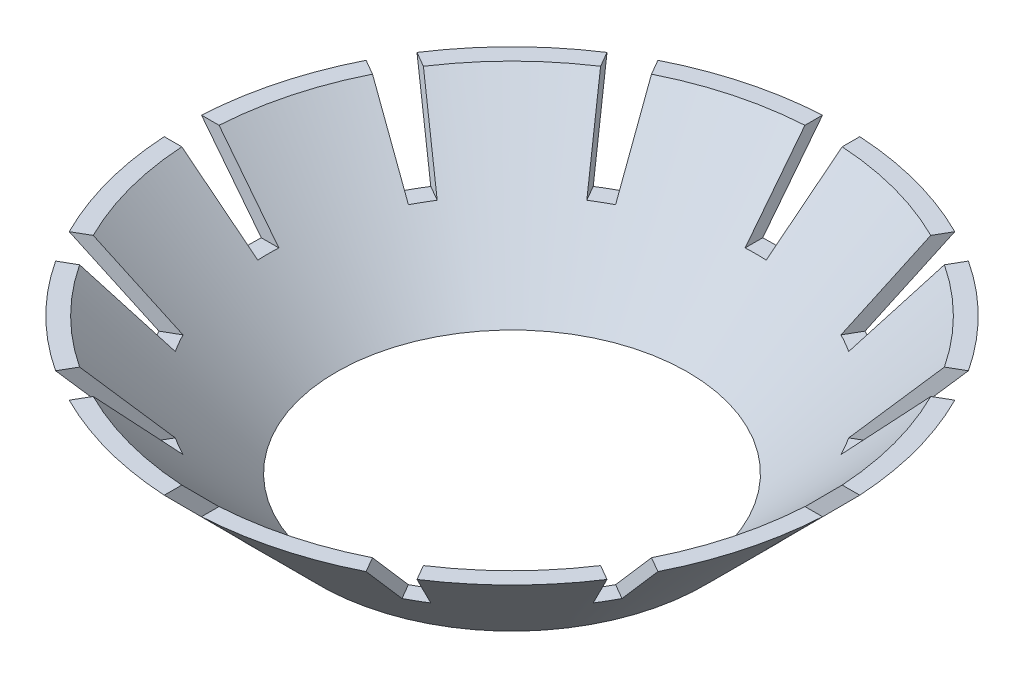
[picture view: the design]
ISO-10303-21;
HEADER;
FILE_DESCRIPTION(('STEP AP214'),'2;1');
FILE_NAME('part.step','',(''),(''),'','','');
FILE_SCHEMA(('AUTOMOTIVE_DESIGN { 1 0 10303 214 1 1 1 1 }'));
ENDSEC;
DATA;
#1=APPLICATION_CONTEXT('core data for automotive mechanical design processes');
#2=APPLICATION_PROTOCOL_DEFINITION('international standard','automotive_design',2000,#1);
#3=PRODUCT_CONTEXT('',#1,'mechanical');
#4=PRODUCT('Part','Part','',(#3));
#5=PRODUCT_RELATED_PRODUCT_CATEGORY('part','',(#4));
#6=PRODUCT_DEFINITION_FORMATION('','',#4);
#7=PRODUCT_DEFINITION_CONTEXT('part definition',#1,'design');
#8=PRODUCT_DEFINITION('design','',#6,#7);
#9=PRODUCT_DEFINITION_SHAPE('','',#8);
#10=(LENGTH_UNIT() NAMED_UNIT(*) SI_UNIT(.MILLI.,.METRE.));
#11=(NAMED_UNIT(*) PLANE_ANGLE_UNIT() SI_UNIT($,.RADIAN.));
#12=(NAMED_UNIT(*) SI_UNIT($,.STERADIAN.) SOLID_ANGLE_UNIT());
#13=UNCERTAINTY_MEASURE_WITH_UNIT(LENGTH_MEASURE(1.E-05),#10,'distance_accuracy_value','');
#14=(GEOMETRIC_REPRESENTATION_CONTEXT(3) GLOBAL_UNCERTAINTY_ASSIGNED_CONTEXT((#13)) GLOBAL_UNIT_ASSIGNED_CONTEXT((#10,
#11,#12)) REPRESENTATION_CONTEXT('',''));
#15=CARTESIAN_POINT('',(0.,0.,0.));
#16=DIRECTION('',(0.,0.,1.));
#17=DIRECTION('',(1.,0.,0.));
#18=AXIS2_PLACEMENT_3D('',#15,#16,#17);
#19=CARTESIAN_POINT('',(0.,6.59999999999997,-15.1));
#20=DIRECTION('',(0.,1.,0.));
#21=DIRECTION('',(0.,0.,1.));
#22=AXIS2_PLACEMENT_3D('',#19,#20,#21);
#23=PLANE('',#22);
#24=DIRECTION('',(0.500000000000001,0.,0.866025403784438));
#25=VECTOR('',#24,1.);
#26=CARTESIAN_POINT('',(-7.31912306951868,6.59999999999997,-10.8743023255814));
#27=LINE('',#26,#25);
#28=CARTESIAN_POINT('',(-8.74214865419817,6.59999999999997,-13.3390549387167));
#29=VERTEX_POINT('',#28);
#30=CARTESIAN_POINT('',(-8.31716705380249,6.59999999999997,-12.6029652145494));
#31=VERTEX_POINT('',#30);
#32=EDGE_CURVE('E690',#29,#31,#27,.T.);
#33=ORIENTED_EDGE('',*,*,#32,.F.);
#34=CARTESIAN_POINT('',(0.,6.59999999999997,0.));
#35=DIRECTION('',(0.,-1.,0.));
#36=DIRECTION('',(0.,0.,-1.));
#37=AXIS2_PLACEMENT_3D('',#34,#35,#36);
#38=CIRCLE('',#37,15.9485281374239);
#39=CARTESIAN_POINT('',(-13.3390549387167,6.59999999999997,-8.74214865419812));
#40=VERTEX_POINT('',#39);
#41=EDGE_CURVE('E799',#40,#29,#38,.T.);
#42=ORIENTED_EDGE('',*,*,#41,.F.);
#43=DIRECTION('',(-0.86602540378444,0.,-0.499999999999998));
#44=VECTOR('',#43,1.);
#45=CARTESIAN_POINT('',(-6.08779412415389,6.59999999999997,-4.55563127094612));
#46=LINE('',#45,#44);
#47=CARTESIAN_POINT('',(-12.6029652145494,6.59999999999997,-8.31716705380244));
#48=VERTEX_POINT('',#47);
#49=EDGE_CURVE('E792',#48,#40,#46,.T.);
#50=ORIENTED_EDGE('',*,*,#49,.F.);
#51=CARTESIAN_POINT('',(0.,6.59999999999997,0.));
#52=DIRECTION('',(0.,-1.,0.));
#53=DIRECTION('',(0.,0.,-1.));
#54=AXIS2_PLACEMENT_3D('',#51,#52,#53);
#55=CIRCLE('',#54,15.1);
#56=EDGE_CURVE('E797',#48,#31,#55,.T.);
#57=ORIENTED_EDGE('',*,*,#56,.T.);
#58=EDGE_LOOP('',(#33,#42,#50,#57));
#59=FACE_BOUND('',#58,.T.);
#60=ADVANCED_FACE('F39',(#59),#23,.T.);
#61=DIRECTION('',(0.86602540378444,0.,0.499999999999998));
#62=VECTOR('',#61,1.);
#63=CARTESIAN_POINT('',(-6.98918947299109,6.59999999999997,-2.99436872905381));
#64=LINE('',#63,#62);
#65=CARTESIAN_POINT('',(-14.2404502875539,6.59999999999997,-7.18088611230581));
#66=VERTEX_POINT('',#65);
#67=CARTESIAN_POINT('',(-13.5043605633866,6.59999999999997,-6.75590451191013));
#68=VERTEX_POINT('',#67);
#69=EDGE_CURVE('E384',#66,#68,#64,.T.);
#70=ORIENTED_EDGE('',*,*,#69,.F.);
#71=CARTESIAN_POINT('',(-15.923034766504,6.59999999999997,-0.901395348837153));
#72=VERTEX_POINT('',#71);
#73=EDGE_CURVE('E830',#72,#66,#38,.T.);
#74=ORIENTED_EDGE('',*,*,#73,.F.);
#75=DIRECTION('',(-1.,0.,0.));
#76=VECTOR('',#75,1.);
#77=CARTESIAN_POINT('',(0.,6.59999999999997,-0.901395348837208));
#78=LINE('',#77,#76);
#79=CARTESIAN_POINT('',(-15.0730715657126,6.59999999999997,-0.901395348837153));
#80=VERTEX_POINT('',#79);
#81=EDGE_CURVE('E1041',#80,#72,#78,.T.);
#82=ORIENTED_EDGE('',*,*,#81,.F.);
#83=EDGE_CURVE('E810',#80,#68,#55,.T.);
#84=ORIENTED_EDGE('',*,*,#83,.T.);
#85=EDGE_LOOP('',(#70,#74,#82,#84));
#86=FACE_BOUND('',#85,.T.);
#87=ADVANCED_FACE('F1086',(#86),#23,.T.);
#88=DIRECTION('',(1.,0.,0.));
#89=VECTOR('',#88,1.);
#90=CARTESIAN_POINT('',(0.,6.59999999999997,0.901395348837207));
#91=LINE('',#90,#89);
#92=CARTESIAN_POINT('',(-15.923034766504,6.59999999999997,0.901395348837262));
#93=VERTEX_POINT('',#92);
#94=CARTESIAN_POINT('',(-15.0730715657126,6.59999999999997,0.901395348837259));
#95=VERTEX_POINT('',#94);
#96=EDGE_CURVE('E1055',#93,#95,#91,.T.);
#97=ORIENTED_EDGE('',*,*,#96,.F.);
#98=CARTESIAN_POINT('',(-14.2404502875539,6.59999999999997,7.18088611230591));
#99=VERTEX_POINT('',#98);
#100=EDGE_CURVE('E827',#99,#93,#38,.T.);
#101=ORIENTED_EDGE('',*,*,#100,.F.);
#102=DIRECTION('',(-0.866025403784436,0.,0.500000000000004));
#103=VECTOR('',#102,1.);
#104=CARTESIAN_POINT('',(6.08779412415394,6.59999999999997,-4.55563127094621));
#105=LINE('',#104,#103);
#106=CARTESIAN_POINT('',(-13.5043605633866,6.59999999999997,6.75590451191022));
#107=VERTEX_POINT('',#106);
#108=EDGE_CURVE('E1012',#107,#99,#105,.T.);
#109=ORIENTED_EDGE('',*,*,#108,.F.);
#110=EDGE_CURVE('E809',#107,#95,#55,.T.);
#111=ORIENTED_EDGE('',*,*,#110,.T.);
#112=EDGE_LOOP('',(#97,#101,#109,#111));
#113=FACE_BOUND('',#112,.T.);
#114=ADVANCED_FACE('F1095',(#113),#23,.T.);
#115=DIRECTION('',(0.866025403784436,0.,-0.500000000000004));
#116=VECTOR('',#115,1.);
#117=CARTESIAN_POINT('',(6.98918947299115,6.59999999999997,-2.9943687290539));
#118=LINE('',#117,#116);
#119=CARTESIAN_POINT('',(-13.3390549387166,6.59999999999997,8.74214865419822));
#120=VERTEX_POINT('',#119);
#121=CARTESIAN_POINT('',(-12.6029652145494,6.59999999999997,8.31716705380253));
#122=VERTEX_POINT('',#121);
#123=EDGE_CURVE('E1036',#120,#122,#118,.T.);
#124=ORIENTED_EDGE('',*,*,#123,.F.);
#125=CARTESIAN_POINT('',(-8.74214865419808,6.59999999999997,13.3390549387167));
#126=VERTEX_POINT('',#125);
#127=EDGE_CURVE('E833',#126,#120,#38,.T.);
#128=ORIENTED_EDGE('',*,*,#127,.F.);
#129=DIRECTION('',(-0.499999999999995,0.,0.866025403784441));
#130=VECTOR('',#129,1.);
#131=CARTESIAN_POINT('',(5.75786052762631,6.59999999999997,-11.7756976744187));
#132=LINE('',#131,#130);
#133=CARTESIAN_POINT('',(-8.3171670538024,6.59999999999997,12.6029652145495));
#134=VERTEX_POINT('',#133);
#135=EDGE_CURVE('E996',#134,#126,#132,.T.);
#136=ORIENTED_EDGE('',*,*,#135,.F.);
#137=EDGE_CURVE('E1094',#134,#122,#55,.T.);
#138=ORIENTED_EDGE('',*,*,#137,.T.);
#139=EDGE_LOOP('',(#124,#128,#136,#138));
#140=FACE_BOUND('',#139,.T.);
#141=ADVANCED_FACE('F1191',(#140),#23,.T.);
#142=DIRECTION('',(0.499999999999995,0.,-0.866025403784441));
#143=VECTOR('',#142,1.);
#144=CARTESIAN_POINT('',(7.31912306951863,6.59999999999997,-10.8743023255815));
#145=LINE('',#144,#143);
#146=CARTESIAN_POINT('',(-7.18088611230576,6.59999999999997,14.2404502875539));
#147=VERTEX_POINT('',#146);
#148=CARTESIAN_POINT('',(-6.75590451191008,6.59999999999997,13.5043605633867));
#149=VERTEX_POINT('',#148);
#150=EDGE_CURVE('E1007',#147,#149,#145,.T.);
#151=ORIENTED_EDGE('',*,*,#150,.F.);
#152=CARTESIAN_POINT('',(-0.901395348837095,6.59999999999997,15.923034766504));
#153=VERTEX_POINT('',#152);
#154=EDGE_CURVE('E836',#153,#147,#38,.T.);
#155=ORIENTED_EDGE('',*,*,#154,.F.);
#156=DIRECTION('',(0.,0.,1.));
#157=VECTOR('',#156,1.);
#158=CARTESIAN_POINT('',(-0.901395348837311,6.59999999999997,-15.1));
#159=LINE('',#158,#157);
#160=CARTESIAN_POINT('',(-0.901395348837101,6.59999999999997,15.0730715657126));
#161=VERTEX_POINT('',#160);
#162=EDGE_CURVE('E968',#161,#153,#159,.T.);
#163=ORIENTED_EDGE('',*,*,#162,.F.);
#164=EDGE_CURVE('E1100',#161,#149,#55,.T.);
#165=ORIENTED_EDGE('',*,*,#164,.T.);
#166=EDGE_LOOP('',(#151,#155,#163,#165));
#167=FACE_BOUND('',#166,.T.);
#168=ADVANCED_FACE('F1189',(#167),#23,.T.);
#169=DIRECTION('',(0.,0.,-1.));
#170=VECTOR('',#169,1.);
#171=CARTESIAN_POINT('',(0.9013953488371,6.59999999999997,-15.1));
#172=LINE('',#171,#170);
#173=CARTESIAN_POINT('',(0.901395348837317,6.59999999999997,15.923034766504));
#174=VERTEX_POINT('',#173);
#175=CARTESIAN_POINT('',(0.901395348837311,6.59999999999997,15.0730715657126));
#176=VERTEX_POINT('',#175);
#177=EDGE_CURVE('E980',#174,#176,#172,.T.);
#178=ORIENTED_EDGE('',*,*,#177,.F.);
#179=CARTESIAN_POINT('',(7.18088611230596,6.59999999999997,14.2404502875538));
#180=VERTEX_POINT('',#179);
#181=EDGE_CURVE('E843',#180,#174,#38,.T.);
#182=ORIENTED_EDGE('',*,*,#181,.F.);
#183=DIRECTION('',(0.500000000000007,0.,0.866025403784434));
#184=VECTOR('',#183,1.);
#185=CARTESIAN_POINT('',(-7.31912306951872,6.59999999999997,-10.8743023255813));
#186=LINE('',#185,#184);
#187=CARTESIAN_POINT('',(6.75590451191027,6.59999999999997,13.5043605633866));
#188=VERTEX_POINT('',#187);
#189=EDGE_CURVE('E934',#188,#180,#186,.T.);
#190=ORIENTED_EDGE('',*,*,#189,.F.);
#191=EDGE_CURVE('E1102',#188,#176,#55,.T.);
#192=ORIENTED_EDGE('',*,*,#191,.T.);
#193=EDGE_LOOP('',(#178,#182,#190,#192));
#194=FACE_BOUND('',#193,.T.);
#195=ADVANCED_FACE('F1186',(#194),#23,.T.);
#196=DIRECTION('',(-0.500000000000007,0.,-0.866025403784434));
#197=VECTOR('',#196,1.);
#198=CARTESIAN_POINT('',(-5.75786052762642,6.59999999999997,-11.7756976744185));
#199=LINE('',#198,#197);
#200=CARTESIAN_POINT('',(8.74214865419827,6.59999999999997,13.3390549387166));
#201=VERTEX_POINT('',#200);
#202=CARTESIAN_POINT('',(8.31716705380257,6.59999999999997,12.6029652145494));
#203=VERTEX_POINT('',#202);
#204=EDGE_CURVE('E965',#201,#203,#199,.T.);
#205=ORIENTED_EDGE('',*,*,#204,.F.);
#206=CARTESIAN_POINT('',(13.3390549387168,6.59999999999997,8.74214865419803));
#207=VERTEX_POINT('',#206);
#208=EDGE_CURVE('E846',#207,#201,#38,.T.);
#209=ORIENTED_EDGE('',*,*,#208,.F.);
#210=DIRECTION('',(0.866025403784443,0.,0.499999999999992));
#211=VECTOR('',#210,1.);
#212=CARTESIAN_POINT('',(-6.98918947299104,6.59999999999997,-2.99436872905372));
#213=LINE('',#212,#211);
#214=CARTESIAN_POINT('',(12.6029652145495,6.59999999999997,8.31716705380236));
#215=VERTEX_POINT('',#214);
#216=EDGE_CURVE('E454',#215,#207,#213,.T.);
#217=ORIENTED_EDGE('',*,*,#216,.F.);
#218=EDGE_CURVE('E1106',#215,#203,#55,.T.);
#219=ORIENTED_EDGE('',*,*,#218,.T.);
#220=EDGE_LOOP('',(#205,#209,#217,#219));
#221=FACE_BOUND('',#220,.T.);
#222=ADVANCED_FACE('F1119',(#221),#23,.T.);
#223=DIRECTION('',(-0.866025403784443,0.,-0.499999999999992));
#224=VECTOR('',#223,1.);
#225=CARTESIAN_POINT('',(-6.08779412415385,6.59999999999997,-4.55563127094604));
#226=LINE('',#225,#224);
#227=CARTESIAN_POINT('',(14.240450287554,6.59999999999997,7.18088611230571));
#228=VERTEX_POINT('',#227);
#229=CARTESIAN_POINT('',(13.5043605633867,6.59999999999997,6.75590451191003));
#230=VERTEX_POINT('',#229);
#231=EDGE_CURVE('E927',#228,#230,#226,.T.);
#232=ORIENTED_EDGE('',*,*,#231,.F.);
#233=CARTESIAN_POINT('',(15.923034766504,6.59999999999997,0.90139534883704));
#234=VERTEX_POINT('',#233);
#235=EDGE_CURVE('E854',#234,#228,#38,.T.);
#236=ORIENTED_EDGE('',*,*,#235,.F.);
#237=DIRECTION('',(1.,0.,0.));
#238=VECTOR('',#237,1.);
#239=CARTESIAN_POINT('',(1.67605719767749E-13,6.59999999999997,0.901395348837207));
#240=LINE('',#239,#238);
#241=CARTESIAN_POINT('',(15.0730715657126,6.59999999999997,0.901395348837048));
#242=VERTEX_POINT('',#241);
#243=EDGE_CURVE('E874',#242,#234,#240,.T.);
#244=ORIENTED_EDGE('',*,*,#243,.F.);
#245=EDGE_CURVE('E918',#242,#230,#55,.T.);
#246=ORIENTED_EDGE('',*,*,#245,.T.);
#247=EDGE_LOOP('',(#232,#236,#244,#246));
#248=FACE_BOUND('',#247,.T.);
#249=ADVANCED_FACE('F921',(#248),#23,.T.);
#250=DIRECTION('',(-1.,0.,0.));
#251=VECTOR('',#250,1.);
#252=CARTESIAN_POINT('',(1.48722489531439E-13,6.59999999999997,-0.901395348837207));
#253=LINE('',#252,#251);
#254=CARTESIAN_POINT('',(15.923034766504,6.59999999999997,-0.901395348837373));
#255=VERTEX_POINT('',#254);
#256=CARTESIAN_POINT('',(15.0730715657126,6.59999999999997,-0.901395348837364));
#257=VERTEX_POINT('',#256);
#258=EDGE_CURVE('E457',#255,#257,#253,.T.);
#259=ORIENTED_EDGE('',*,*,#258,.F.);
#260=CARTESIAN_POINT('',(14.2404502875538,6.59999999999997,-7.18088611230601));
#261=VERTEX_POINT('',#260);
#262=EDGE_CURVE('E453',#261,#255,#38,.T.);
#263=ORIENTED_EDGE('',*,*,#262,.F.);
#264=DIRECTION('',(0.866025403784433,0.,-0.50000000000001));
#265=VECTOR('',#264,1.);
#266=CARTESIAN_POINT('',(6.98918947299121,6.59999999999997,-2.994368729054));
#267=LINE('',#266,#265);
#268=CARTESIAN_POINT('',(13.5043605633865,6.59999999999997,-6.75590451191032));
#269=VERTEX_POINT('',#268);
#270=EDGE_CURVE('E878',#269,#261,#267,.T.);
#271=ORIENTED_EDGE('',*,*,#270,.F.);
#272=EDGE_CURVE('E911',#269,#257,#55,.T.);
#273=ORIENTED_EDGE('',*,*,#272,.T.);
#274=EDGE_LOOP('',(#259,#263,#271,#273));
#275=FACE_BOUND('',#274,.T.);
#276=ADVANCED_FACE('F915',(#275),#23,.T.);
#277=DIRECTION('',(-0.866025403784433,0.,0.50000000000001));
#278=VECTOR('',#277,1.);
#279=CARTESIAN_POINT('',(6.08779412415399,6.59999999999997,-4.5556312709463));
#280=LINE('',#279,#278);
#281=CARTESIAN_POINT('',(13.3390549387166,6.59999999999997,-8.74214865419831));
#282=VERTEX_POINT('',#281);
#283=CARTESIAN_POINT('',(12.6029652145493,6.59999999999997,-8.31716705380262));
#284=VERTEX_POINT('',#283);
#285=EDGE_CURVE('E866',#282,#284,#280,.T.);
#286=ORIENTED_EDGE('',*,*,#285,.F.);
#287=CARTESIAN_POINT('',(8.74214865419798,6.59999999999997,-13.3390549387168));
#288=VERTEX_POINT('',#287);
#289=EDGE_CURVE('E742',#288,#282,#38,.T.);
#290=ORIENTED_EDGE('',*,*,#289,.F.);
#291=DIRECTION('',(0.499999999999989,0.,-0.866025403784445));
#292=VECTOR('',#291,1.);
#293=CARTESIAN_POINT('',(7.31912306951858,6.59999999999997,-10.8743023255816));
#294=LINE('',#293,#292);
#295=CARTESIAN_POINT('',(8.31716705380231,6.59999999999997,-12.6029652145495));
#296=VERTEX_POINT('',#295);
#297=EDGE_CURVE('E354',#296,#288,#294,.T.);
#298=ORIENTED_EDGE('',*,*,#297,.F.);
#299=EDGE_CURVE('E739',#296,#284,#55,.T.);
#300=ORIENTED_EDGE('',*,*,#299,.T.);
#301=EDGE_LOOP('',(#286,#290,#298,#300));
#302=FACE_BOUND('',#301,.T.);
#303=ADVANCED_FACE('F867',(#302),#23,.T.);
#304=DIRECTION('',(-0.499999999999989,0.,0.866025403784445));
#305=VECTOR('',#304,1.);
#306=CARTESIAN_POINT('',(5.75786052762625,6.59999999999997,-11.7756976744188));
#307=LINE('',#306,#305);
#308=CARTESIAN_POINT('',(7.18088611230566,6.59999999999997,-14.240450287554));
#309=VERTEX_POINT('',#308);
#310=CARTESIAN_POINT('',(6.75590451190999,6.59999999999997,-13.5043605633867));
#311=VERTEX_POINT('',#310);
#312=EDGE_CURVE('E360',#309,#311,#307,.T.);
#313=ORIENTED_EDGE('',*,*,#312,.F.);
#314=CARTESIAN_POINT('',(0.901395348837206,6.59999999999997,-15.923034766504));
#315=VERTEX_POINT('',#314);
#316=EDGE_CURVE('E740',#315,#309,#38,.T.);
#317=ORIENTED_EDGE('',*,*,#316,.F.);
#318=DIRECTION('',(0.,0.,-1.));
#319=VECTOR('',#318,1.);
#320=CARTESIAN_POINT('',(0.901395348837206,6.59999999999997,-15.1));
#321=LINE('',#320,#319);
#322=CARTESIAN_POINT('',(0.901395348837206,6.59999999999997,-15.0730715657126));
#323=VERTEX_POINT('',#322);
#324=EDGE_CURVE('E720',#323,#315,#321,.T.);
#325=ORIENTED_EDGE('',*,*,#324,.F.);
#326=EDGE_CURVE('E732',#323,#311,#55,.T.);
#327=ORIENTED_EDGE('',*,*,#326,.T.);
#328=EDGE_LOOP('',(#313,#317,#325,#327));
#329=FACE_BOUND('',#328,.T.);
#330=ADVANCED_FACE('F821',(#329),#23,.T.);
#331=CARTESIAN_POINT('',(0.,0.,-8.5));
#332=DIRECTION('',(0.,-1.,0.));
#333=DIRECTION('',(0.,0.,-1.));
#334=AXIS2_PLACEMENT_3D('',#331,#332,#333);
#335=PLANE('',#334);
#336=CARTESIAN_POINT('',(0.,0.,0.));
#337=DIRECTION('',(0.,-1.,0.));
#338=DIRECTION('',(0.,0.,-1.));
#339=AXIS2_PLACEMENT_3D('',#336,#337,#338);
#340=CIRCLE('',#339,9.34852813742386);
#341=CARTESIAN_POINT('',(0.,0.,-9.34852813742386));
#342=VERTEX_POINT('',#341);
#343=EDGE_CURVE('E738',#342,#342,#340,.T.);
#344=ORIENTED_EDGE('',*,*,#343,.T.);
#345=EDGE_LOOP('',(#344));
#346=FACE_BOUND('',#345,.T.);
#347=CARTESIAN_POINT('',(0.,0.,0.));
#348=DIRECTION('',(0.,-1.,0.));
#349=DIRECTION('',(0.,0.,-1.));
#350=AXIS2_PLACEMENT_3D('',#347,#348,#349);
#351=CIRCLE('',#350,8.5);
#352=CARTESIAN_POINT('',(0.,0.,-8.5));
#353=VERTEX_POINT('',#352);
#354=EDGE_CURVE('E729',#353,#353,#351,.T.);
#355=ORIENTED_EDGE('',*,*,#354,.F.);
#356=EDGE_LOOP('',(#355));
#357=FACE_BOUND('',#356,.T.);
#358=ADVANCED_FACE('F41',(#346,#357),#335,.T.);
#359=CARTESIAN_POINT('',(0.,0.,0.));
#360=DIRECTION('',(0.,1.,0.));
#361=DIRECTION('',(0.,0.,1.));
#362=AXIS2_PLACEMENT_3D('',#359,#360,#361);
#363=CONICAL_SURFACE('',#362,9.34852813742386,0.78539816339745);
#364=CARTESIAN_POINT('',(-6.7606738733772,3.2998,-10.6898780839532));
#365=CARTESIAN_POINT('',(-7.09100219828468,3.8497129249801,-11.1315790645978));
#366=CARTESIAN_POINT('',(-7.42129926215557,4.39970272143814,-11.573207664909));
#367=CARTESIAN_POINT('',(-8.08183086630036,5.49983605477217,-12.4563201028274));
#368=CARTESIAN_POINT('',(-8.41206540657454,6.04997959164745,-12.8978039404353));
#369=CARTESIAN_POINT('',(-8.74226868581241,6.60019999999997,-13.3392153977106));
#370=B_SPLINE_CURVE_WITH_KNOTS('',3,(#364,#365,#366,#367,#368,#369),.UNSPECIFIED.,.F.,.F.,(4,2,
4),(0.,2.33657585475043,4.67315169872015),.UNSPECIFIED.);
#371=CARTESIAN_POINT('',(-6.76079401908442,3.3,-10.690038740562));
#372=VERTEX_POINT('',#371);
#373=EDGE_CURVE('E689',#372,#29,#370,.T.);
#374=ORIENTED_EDGE('',*,*,#373,.F.);
#375=CARTESIAN_POINT('',(0.,3.3,0.));
#376=DIRECTION('',(0.,-1.,0.));
#377=DIRECTION('',(0.,0.,-1.));
#378=AXIS2_PLACEMENT_3D('',#375,#376,#377);
#379=CIRCLE('',#378,12.6485281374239);
#380=CARTESIAN_POINT('',(-5.87744810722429,3.3,-11.200038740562));
#381=VERTEX_POINT('',#380);
#382=EDGE_CURVE('E382',#381,#372,#379,.F.);
#383=ORIENTED_EDGE('',*,*,#382,.F.);
#384=CARTESIAN_POINT('',(-7.18096505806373,6.60019999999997,-14.240634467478));
#385=CARTESIAN_POINT('',(-6.96379316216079,6.04997959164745,-13.7339643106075));
#386=CARTESIAN_POINT('',(-6.74657421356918,5.49983605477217,-13.227230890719));
#387=CARTESIAN_POINT('',(-6.31204221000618,4.39970272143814,-12.2136375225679));
#388=CARTESIAN_POINT('',(-6.09472915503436,3.84971292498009,-11.7067775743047));
#389=CARTESIAN_POINT('',(-5.87736904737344,3.2998,-11.199854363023));
#390=B_SPLINE_CURVE_WITH_KNOTS('',3,(#384,#385,#386,#387,#388,#389),.UNSPECIFIED.,.F.,.F.,(4,2,
4),(0.,2.33657584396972,4.67315169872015),.UNSPECIFIED.);
#391=CARTESIAN_POINT('',(-7.18088611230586,6.59999999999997,-14.2404502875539));
#392=VERTEX_POINT('',#391);
#393=EDGE_CURVE('E389',#392,#381,#390,.T.);
#394=ORIENTED_EDGE('',*,*,#393,.F.);
#395=CARTESIAN_POINT('',(-0.901395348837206,6.59999999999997,-15.923034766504));
#396=VERTEX_POINT('',#395);
#397=EDGE_CURVE('E737',#392,#396,#38,.T.);
#398=ORIENTED_EDGE('',*,*,#397,.T.);
#399=CARTESIAN_POINT('',(-0.509976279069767,3.2998,-12.6380429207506));
#400=CARTESIAN_POINT('',(-0.575198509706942,3.84971292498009,-13.185731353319));
#401=CARTESIAN_POINT('',(-0.640429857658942,4.39970272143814,-13.7333414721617));
#402=CARTESIAN_POINT('',(-0.770910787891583,5.49983605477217,-14.8284050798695));
#403=CARTESIAN_POINT('',(-0.83616037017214,6.04997959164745,-15.3758585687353));
#404=CARTESIAN_POINT('',(-0.901419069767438,6.60019999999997,-15.9232337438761));
#405=B_SPLINE_CURVE_WITH_KNOTS('',3,(#399,#400,#401,#402,#403,#404),.UNSPECIFIED.,.F.,.F.,(4,2,
4),(0.,2.33657585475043,4.67315169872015),.UNSPECIFIED.);
#406=CARTESIAN_POINT('',(-0.51,3.3,-12.6382421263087));
#407=VERTEX_POINT('',#406);
#408=EDGE_CURVE('E725',#407,#396,#405,.T.);
#409=ORIENTED_EDGE('',*,*,#408,.F.);
#410=CARTESIAN_POINT('',(0.,3.3,0.));
#411=DIRECTION('',(0.,-1.,0.));
#412=DIRECTION('',(0.,0.,-1.));
#413=AXIS2_PLACEMENT_3D('',#410,#411,#412);
#414=CIRCLE('',#413,12.6485281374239);
#415=CARTESIAN_POINT('',(0.51,3.3,-12.6382421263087));
#416=VERTEX_POINT('',#415);
#417=EDGE_CURVE('E822',#416,#407,#414,.F.);
#418=ORIENTED_EDGE('',*,*,#417,.F.);
#419=CARTESIAN_POINT('',(0.901419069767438,6.60019999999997,-15.9232337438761));
#420=CARTESIAN_POINT('',(0.83616037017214,6.04997959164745,-15.3758585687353));
#421=CARTESIAN_POINT('',(0.770910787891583,5.49983605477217,-14.8284050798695));
#422=CARTESIAN_POINT('',(0.640429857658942,4.39970272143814,-13.7333414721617));
#423=CARTESIAN_POINT('',(0.575198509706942,3.84971292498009,-13.185731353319));
#424=CARTESIAN_POINT('',(0.509976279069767,3.2998,-12.6380429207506));
#425=B_SPLINE_CURVE_WITH_KNOTS('',3,(#419,#420,#421,#422,#423,#424),.UNSPECIFIED.,.F.,.F.,(4,2,
4),(0.,2.33657584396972,4.67315169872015),.UNSPECIFIED.);
#426=EDGE_CURVE('E708',#315,#416,#425,.T.);
#427=ORIENTED_EDGE('',*,*,#426,.F.);
#428=ORIENTED_EDGE('',*,*,#316,.T.);
#429=CARTESIAN_POINT('',(5.87736904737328,3.2998,-11.1998543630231));
#430=CARTESIAN_POINT('',(6.0947291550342,3.8497129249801,-11.7067775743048));
#431=CARTESIAN_POINT('',(6.31204221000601,4.39970272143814,-12.213637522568));
#432=CARTESIAN_POINT('',(6.746574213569,5.49983605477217,-13.2272308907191));
#433=CARTESIAN_POINT('',(6.9637931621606,6.04997959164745,-13.7339643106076));
#434=CARTESIAN_POINT('',(7.18096505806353,6.60019999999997,-14.2406344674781));
#435=B_SPLINE_CURVE_WITH_KNOTS('',3,(#429,#430,#431,#432,#433,#434),.UNSPECIFIED.,.F.,.F.,(4,2,
4),(0.,2.33657585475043,4.67315169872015),.UNSPECIFIED.);
#436=CARTESIAN_POINT('',(5.87744810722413,3.3,-11.2000387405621));
#437=VERTEX_POINT('',#436);
#438=EDGE_CURVE('E380',#437,#309,#435,.T.);
#439=ORIENTED_EDGE('',*,*,#438,.F.);
#440=CARTESIAN_POINT('',(6.76079401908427,3.3,-10.6900387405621));
#441=VERTEX_POINT('',#440);
#442=EDGE_CURVE('E364',#441,#437,#379,.F.);
#443=ORIENTED_EDGE('',*,*,#442,.F.);
#444=CARTESIAN_POINT('',(8.74226868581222,6.60019999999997,-13.3392153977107));
#445=CARTESIAN_POINT('',(8.41206540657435,6.04997959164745,-12.8978039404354));
#446=CARTESIAN_POINT('',(8.08183086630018,5.49983605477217,-12.4563201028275));
#447=CARTESIAN_POINT('',(7.42129926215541,4.39970272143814,-11.5732076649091));
#448=CARTESIAN_POINT('',(7.09100219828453,3.8497129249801,-11.1315790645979));
#449=CARTESIAN_POINT('',(6.76067387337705,3.2998,-10.6898780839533));
#450=B_SPLINE_CURVE_WITH_KNOTS('',3,(#444,#445,#446,#447,#448,#449),.UNSPECIFIED.,.F.,.F.,(4,2,
4),(0.,2.33657584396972,4.67315169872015),.UNSPECIFIED.);
#451=EDGE_CURVE('E350',#288,#441,#450,.T.);
#452=ORIENTED_EDGE('',*,*,#451,.F.);
#453=ORIENTED_EDGE('',*,*,#289,.T.);
#454=CARTESIAN_POINT('',(10.6898780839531,3.2998,-6.76067387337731));
#455=CARTESIAN_POINT('',(11.1315790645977,3.8497129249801,-7.0910021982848));
#456=CARTESIAN_POINT('',(11.5732076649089,4.39970272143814,-7.42129926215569));
#457=CARTESIAN_POINT('',(12.4563201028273,5.49983605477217,-8.08183086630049));
#458=CARTESIAN_POINT('',(12.8978039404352,6.04997959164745,-8.41206540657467));
#459=CARTESIAN_POINT('',(13.3392153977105,6.60019999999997,-8.74226868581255));
#460=B_SPLINE_CURVE_WITH_KNOTS('',3,(#454,#455,#456,#457,#458,#459),.UNSPECIFIED.,.F.,.F.,(4,2,
4),(0.,2.33657585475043,4.67315169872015),.UNSPECIFIED.);
#461=CARTESIAN_POINT('',(10.6900387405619,3.3,-6.76079401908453));
#462=VERTEX_POINT('',#461);
#463=EDGE_CURVE('E862',#462,#282,#460,.T.);
#464=ORIENTED_EDGE('',*,*,#463,.F.);
#465=CARTESIAN_POINT('',(11.2000387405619,3.3,-5.87744810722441));
#466=VERTEX_POINT('',#465);
#467=EDGE_CURVE('E377',#466,#462,#379,.F.);
#468=ORIENTED_EDGE('',*,*,#467,.F.);
#469=CARTESIAN_POINT('',(14.2406344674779,6.60019999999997,-7.18096505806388));
#470=CARTESIAN_POINT('',(13.7339643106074,6.04997959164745,-6.96379316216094));
#471=CARTESIAN_POINT('',(13.2272308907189,5.49983605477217,-6.74657421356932));
#472=CARTESIAN_POINT('',(12.2136375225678,4.39970272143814,-6.31204221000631));
#473=CARTESIAN_POINT('',(11.7067775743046,3.8497129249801,-6.09472915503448));
#474=CARTESIAN_POINT('',(11.1998543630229,3.2998,-5.87736904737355));
#475=B_SPLINE_CURVE_WITH_KNOTS('',3,(#469,#470,#471,#472,#473,#474),.UNSPECIFIED.,.F.,.F.,(4,2,
4),(0.,2.33657584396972,4.67315169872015),.UNSPECIFIED.);
#476=EDGE_CURVE('E875',#261,#466,#475,.T.);
#477=ORIENTED_EDGE('',*,*,#476,.F.);
#478=ORIENTED_EDGE('',*,*,#262,.T.);
#479=CARTESIAN_POINT('',(12.6380429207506,3.2998,-0.5099762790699));
#480=CARTESIAN_POINT('',(13.185731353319,3.8497129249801,-0.57519850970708));
#481=CARTESIAN_POINT('',(13.7333414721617,4.39970272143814,-0.640429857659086));
#482=CARTESIAN_POINT('',(14.8284050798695,5.49983605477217,-0.770910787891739));
#483=CARTESIAN_POINT('',(15.3758585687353,6.04997959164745,-0.836160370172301));
#484=CARTESIAN_POINT('',(15.9232337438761,6.60019999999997,-0.901419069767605));
#485=B_SPLINE_CURVE_WITH_KNOTS('',3,(#479,#480,#481,#482,#483,#484),.UNSPECIFIED.,.F.,.F.,(4,2,
4),(0.,2.33657585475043,4.67315169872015),.UNSPECIFIED.);
#486=CARTESIAN_POINT('',(12.6382421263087,3.3,-0.510000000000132));
#487=VERTEX_POINT('',#486);
#488=EDGE_CURVE('E444',#487,#255,#485,.T.);
#489=ORIENTED_EDGE('',*,*,#488,.F.);
#490=CARTESIAN_POINT('',(12.6382421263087,3.3,0.509999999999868));
#491=VERTEX_POINT('',#490);
#492=EDGE_CURVE('E385',#491,#487,#379,.F.);
#493=ORIENTED_EDGE('',*,*,#492,.F.);
#494=CARTESIAN_POINT('',(15.9232337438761,6.60019999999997,0.901419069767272));
#495=CARTESIAN_POINT('',(15.3758585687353,6.04997959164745,0.836160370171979));
#496=CARTESIAN_POINT('',(14.8284050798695,5.49983605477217,0.770910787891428));
#497=CARTESIAN_POINT('',(13.7333414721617,4.39970272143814,0.640429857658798));
#498=CARTESIAN_POINT('',(13.185731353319,3.84971292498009,0.575198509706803));
#499=CARTESIAN_POINT('',(12.6380429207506,3.2998,0.509976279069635));
#500=B_SPLINE_CURVE_WITH_KNOTS('',3,(#494,#495,#496,#497,#498,#499),.UNSPECIFIED.,.F.,.F.,(4,2,
4),(0.,2.33657584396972,4.67315169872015),.UNSPECIFIED.);
#501=EDGE_CURVE('E458',#234,#491,#500,.T.);
#502=ORIENTED_EDGE('',*,*,#501,.F.);
#503=ORIENTED_EDGE('',*,*,#235,.T.);
#504=CARTESIAN_POINT('',(11.1998543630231,3.2998,5.87736904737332));
#505=CARTESIAN_POINT('',(11.7067775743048,3.8497129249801,6.09472915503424));
#506=CARTESIAN_POINT('',(12.213637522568,4.39970272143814,6.31204221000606));
#507=CARTESIAN_POINT('',(13.2272308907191,5.49983605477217,6.74657421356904));
#508=CARTESIAN_POINT('',(13.7339643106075,6.04997959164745,6.96379316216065));
#509=CARTESIAN_POINT('',(14.2406344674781,6.60019999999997,7.18096505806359));
#510=B_SPLINE_CURVE_WITH_KNOTS('',3,(#504,#505,#506,#507,#508,#509),.UNSPECIFIED.,.F.,.F.,(4,2,
4),(0.,2.33657585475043,4.67315169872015),.UNSPECIFIED.);
#511=CARTESIAN_POINT('',(11.200038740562,3.3,5.87744810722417));
#512=VERTEX_POINT('',#511);
#513=EDGE_CURVE('E929',#512,#228,#510,.T.);
#514=ORIENTED_EDGE('',*,*,#513,.F.);
#515=CARTESIAN_POINT('',(10.690038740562,3.3,6.76079401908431));
#516=VERTEX_POINT('',#515);
#517=EDGE_CURVE('E416',#516,#512,#379,.F.);
#518=ORIENTED_EDGE('',*,*,#517,.F.);
#519=CARTESIAN_POINT('',(13.3392153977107,6.60019999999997,8.74226868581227));
#520=CARTESIAN_POINT('',(12.8978039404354,6.04997959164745,8.4120654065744));
#521=CARTESIAN_POINT('',(12.4563201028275,5.49983605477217,8.08183086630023));
#522=CARTESIAN_POINT('',(11.573207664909,4.39970272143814,7.42129926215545));
#523=CARTESIAN_POINT('',(11.1315790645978,3.8497129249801,7.09100219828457));
#524=CARTESIAN_POINT('',(10.6898780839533,3.2998,6.76067387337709));
#525=B_SPLINE_CURVE_WITH_KNOTS('',3,(#519,#520,#521,#522,#523,#524),.UNSPECIFIED.,.F.,.F.,(4,2,
4),(0.,2.33657584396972,4.67315169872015),.UNSPECIFIED.);
#526=EDGE_CURVE('E460',#207,#516,#525,.T.);
#527=ORIENTED_EDGE('',*,*,#526,.F.);
#528=ORIENTED_EDGE('',*,*,#208,.T.);
#529=CARTESIAN_POINT('',(6.76067387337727,3.2998,10.6898780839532));
#530=CARTESIAN_POINT('',(7.09100219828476,3.8497129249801,11.1315790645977));
#531=CARTESIAN_POINT('',(7.42129926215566,4.39970272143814,11.5732076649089));
#532=CARTESIAN_POINT('',(8.08183086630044,5.49983605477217,12.4563201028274));
#533=CARTESIAN_POINT('',(8.41206540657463,6.04997959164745,12.8978039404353));
#534=CARTESIAN_POINT('',(8.74226868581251,6.60019999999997,13.3392153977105));
#535=B_SPLINE_CURVE_WITH_KNOTS('',3,(#529,#530,#531,#532,#533,#534),.UNSPECIFIED.,.F.,.F.,(4,2,
4),(0.,2.33657585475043,4.67315169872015),.UNSPECIFIED.);
#536=CARTESIAN_POINT('',(6.76079401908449,3.3,10.6900387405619));
#537=VERTEX_POINT('',#536);
#538=EDGE_CURVE('E963',#537,#201,#535,.T.);
#539=ORIENTED_EDGE('',*,*,#538,.F.);
#540=CARTESIAN_POINT('',(5.87744810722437,3.3,11.2000387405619));
#541=VERTEX_POINT('',#540);
#542=EDGE_CURVE('E411',#541,#537,#379,.F.);
#543=ORIENTED_EDGE('',*,*,#542,.F.);
#544=CARTESIAN_POINT('',(7.18096505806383,6.60019999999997,14.240634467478));
#545=CARTESIAN_POINT('',(6.96379316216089,6.04997959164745,13.7339643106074));
#546=CARTESIAN_POINT('',(6.74657421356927,5.49983605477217,13.2272308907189));
#547=CARTESIAN_POINT('',(6.31204221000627,4.39970272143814,12.2136375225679));
#548=CARTESIAN_POINT('',(6.09472915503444,3.8497129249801,11.7067775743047));
#549=CARTESIAN_POINT('',(5.87736904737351,3.2998,11.1998543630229));
#550=B_SPLINE_CURVE_WITH_KNOTS('',3,(#544,#545,#546,#547,#548,#549),.UNSPECIFIED.,.F.,.F.,(4,2,
4),(0.,2.33657584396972,4.67315169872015),.UNSPECIFIED.);
#551=EDGE_CURVE('E956',#180,#541,#550,.T.);
#552=ORIENTED_EDGE('',*,*,#551,.F.);
#553=ORIENTED_EDGE('',*,*,#181,.T.);
#554=CARTESIAN_POINT('',(0.509976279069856,3.2998,12.6380429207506));
#555=CARTESIAN_POINT('',(0.575198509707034,3.8497129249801,13.185731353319));
#556=CARTESIAN_POINT('',(0.640429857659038,4.39970272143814,13.7333414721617));
#557=CARTESIAN_POINT('',(0.770910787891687,5.49983605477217,14.8284050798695));
#558=CARTESIAN_POINT('',(0.836160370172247,6.04997959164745,15.3758585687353));
#559=CARTESIAN_POINT('',(0.90141906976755,6.60019999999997,15.9232337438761));
#560=B_SPLINE_CURVE_WITH_KNOTS('',3,(#554,#555,#556,#557,#558,#559),.UNSPECIFIED.,.F.,.F.,(4,2,
4),(0.,2.33657585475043,4.67315169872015),.UNSPECIFIED.);
#561=CARTESIAN_POINT('',(0.510000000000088,3.3,12.6382421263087));
#562=VERTEX_POINT('',#561);
#563=EDGE_CURVE('E992',#562,#174,#560,.T.);
#564=ORIENTED_EDGE('',*,*,#563,.F.);
#565=CARTESIAN_POINT('',(-0.509999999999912,3.3,12.6382421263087));
#566=VERTEX_POINT('',#565);
#567=EDGE_CURVE('E407',#566,#562,#379,.F.);
#568=ORIENTED_EDGE('',*,*,#567,.F.);
#569=CARTESIAN_POINT('',(-0.901419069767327,6.60019999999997,15.9232337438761));
#570=CARTESIAN_POINT('',(-0.836160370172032,6.04997959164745,15.3758585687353));
#571=CARTESIAN_POINT('',(-0.77091078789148,5.49983605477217,14.8284050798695));
#572=CARTESIAN_POINT('',(-0.640429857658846,4.39970272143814,13.7333414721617));
#573=CARTESIAN_POINT('',(-0.575198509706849,3.84971292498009,13.185731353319));
#574=CARTESIAN_POINT('',(-0.509976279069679,3.2998,12.6380429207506));
#575=B_SPLINE_CURVE_WITH_KNOTS('',3,(#569,#570,#571,#572,#573,#574),.UNSPECIFIED.,.F.,.F.,(4,2,
4),(0.,2.33657584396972,4.67315169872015),.UNSPECIFIED.);
#576=EDGE_CURVE('E975',#153,#566,#575,.T.);
#577=ORIENTED_EDGE('',*,*,#576,.F.);
#578=ORIENTED_EDGE('',*,*,#154,.T.);
#579=CARTESIAN_POINT('',(-5.87736904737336,3.2998,11.199854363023));
#580=CARTESIAN_POINT('',(-6.09472915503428,3.8497129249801,11.7067775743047));
#581=CARTESIAN_POINT('',(-6.3120422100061,4.39970272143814,12.2136375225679));
#582=CARTESIAN_POINT('',(-6.74657421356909,5.49983605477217,13.227230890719));
#583=CARTESIAN_POINT('',(-6.9637931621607,6.04997959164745,13.7339643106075));
#584=CARTESIAN_POINT('',(-7.18096505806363,6.60019999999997,14.2406344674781));
#585=B_SPLINE_CURVE_WITH_KNOTS('',3,(#579,#580,#581,#582,#583,#584),.UNSPECIFIED.,.F.,.F.,(4,2,
4),(0.,2.33657585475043,4.67315169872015),.UNSPECIFIED.);
#586=CARTESIAN_POINT('',(-5.87744810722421,3.3,11.200038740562));
#587=VERTEX_POINT('',#586);
#588=EDGE_CURVE('E1010',#587,#147,#585,.T.);
#589=ORIENTED_EDGE('',*,*,#588,.F.);
#590=CARTESIAN_POINT('',(-6.76079401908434,3.3,10.690038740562));
#591=VERTEX_POINT('',#590);
#592=EDGE_CURVE('E405',#591,#587,#379,.F.);
#593=ORIENTED_EDGE('',*,*,#592,.F.);
#594=CARTESIAN_POINT('',(-8.74226868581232,6.60019999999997,13.3392153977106));
#595=CARTESIAN_POINT('',(-8.41206540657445,6.04997959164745,12.8978039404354));
#596=CARTESIAN_POINT('',(-8.08183086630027,5.49983605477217,12.4563201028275));
#597=CARTESIAN_POINT('',(-7.42129926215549,4.39970272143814,11.573207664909));
#598=CARTESIAN_POINT('',(-7.0910021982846,3.8497129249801,11.1315790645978));
#599=CARTESIAN_POINT('',(-6.76067387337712,3.2998,10.6898780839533));
#600=B_SPLINE_CURVE_WITH_KNOTS('',3,(#594,#595,#596,#597,#598,#599),.UNSPECIFIED.,.F.,.F.,(4,2,
4),(0.,2.33657584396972,4.67315169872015),.UNSPECIFIED.);
#601=EDGE_CURVE('E1002',#126,#591,#600,.T.);
#602=ORIENTED_EDGE('',*,*,#601,.F.);
#603=ORIENTED_EDGE('',*,*,#127,.T.);
#604=CARTESIAN_POINT('',(-10.6898780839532,3.2998,6.76067387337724));
#605=CARTESIAN_POINT('',(-11.1315790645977,3.8497129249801,7.09100219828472));
#606=CARTESIAN_POINT('',(-11.5732076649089,4.39970272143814,7.42129926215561));
#607=CARTESIAN_POINT('',(-12.4563201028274,5.49983605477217,8.0818308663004));
#608=CARTESIAN_POINT('',(-12.8978039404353,6.04997959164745,8.41206540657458));
#609=CARTESIAN_POINT('',(-13.3392153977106,6.60019999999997,8.74226868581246));
#610=B_SPLINE_CURVE_WITH_KNOTS('',3,(#604,#605,#606,#607,#608,#609),.UNSPECIFIED.,.F.,.F.,(4,2,
4),(0.,2.33657585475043,4.67315169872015),.UNSPECIFIED.);
#611=CARTESIAN_POINT('',(-10.6900387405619,3.3,6.76079401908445));
#612=VERTEX_POINT('',#611);
#613=EDGE_CURVE('E1037',#612,#120,#610,.T.);
#614=ORIENTED_EDGE('',*,*,#613,.F.);
#615=CARTESIAN_POINT('',(-11.2000387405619,3.3,5.87744810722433));
#616=VERTEX_POINT('',#615);
#617=EDGE_CURVE('E397',#616,#612,#379,.F.);
#618=ORIENTED_EDGE('',*,*,#617,.F.);
#619=CARTESIAN_POINT('',(-14.240634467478,6.60019999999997,7.18096505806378));
#620=CARTESIAN_POINT('',(-13.7339643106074,6.04997959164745,6.96379316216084));
#621=CARTESIAN_POINT('',(-13.227230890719,5.49983605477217,6.74657421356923));
#622=CARTESIAN_POINT('',(-12.2136375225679,4.39970272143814,6.31204221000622));
#623=CARTESIAN_POINT('',(-11.7067775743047,3.8497129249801,6.0947291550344));
#624=CARTESIAN_POINT('',(-11.199854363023,3.2998,5.87736904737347));
#625=B_SPLINE_CURVE_WITH_KNOTS('',3,(#619,#620,#621,#622,#623,#624),.UNSPECIFIED.,.F.,.F.,(4,2,
4),(0.,2.33657584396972,4.67315169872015),.UNSPECIFIED.);
#626=EDGE_CURVE('E1029',#99,#616,#625,.T.);
#627=ORIENTED_EDGE('',*,*,#626,.F.);
#628=ORIENTED_EDGE('',*,*,#100,.T.);
#629=CARTESIAN_POINT('',(-12.6380429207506,3.2998,0.509976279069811));
#630=CARTESIAN_POINT('',(-13.185731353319,3.8497129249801,0.575198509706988));
#631=CARTESIAN_POINT('',(-13.7333414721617,4.39970272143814,0.64042985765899));
#632=CARTESIAN_POINT('',(-14.8284050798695,5.49983605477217,0.770910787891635));
#633=CARTESIAN_POINT('',(-15.3758585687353,6.04997959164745,0.836160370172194));
#634=CARTESIAN_POINT('',(-15.9232337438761,6.60019999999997,0.901419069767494));
#635=B_SPLINE_CURVE_WITH_KNOTS('',3,(#629,#630,#631,#632,#633,#634),.UNSPECIFIED.,.F.,.F.,(4,2,
4),(0.,2.33657585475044,4.67315169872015),.UNSPECIFIED.);
#636=CARTESIAN_POINT('',(-12.6382421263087,3.3,0.510000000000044));
#637=VERTEX_POINT('',#636);
#638=EDGE_CURVE('E804',#637,#93,#635,.T.);
#639=ORIENTED_EDGE('',*,*,#638,.F.);
#640=CARTESIAN_POINT('',(-12.6382421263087,3.3,-0.509999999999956));
#641=VERTEX_POINT('',#640);
#642=EDGE_CURVE('E392',#641,#637,#379,.F.);
#643=ORIENTED_EDGE('',*,*,#642,.F.);
#644=CARTESIAN_POINT('',(-15.9232337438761,6.60019999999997,-0.901419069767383));
#645=CARTESIAN_POINT('',(-15.3758585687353,6.04997959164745,-0.836160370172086));
#646=CARTESIAN_POINT('',(-14.8284050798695,5.49983605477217,-0.770910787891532));
#647=CARTESIAN_POINT('',(-13.7333414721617,4.39970272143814,-0.640429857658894));
#648=CARTESIAN_POINT('',(-13.185731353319,3.84971292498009,-0.575198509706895));
#649=CARTESIAN_POINT('',(-12.6380429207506,3.2998,-0.509976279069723));
#650=B_SPLINE_CURVE_WITH_KNOTS('',3,(#644,#645,#646,#647,#648,#649),.UNSPECIFIED.,.F.,.F.,(4,2,
4),(0.,2.33657584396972,4.67315169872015),.UNSPECIFIED.);
#651=EDGE_CURVE('E1047',#72,#641,#650,.T.);
#652=ORIENTED_EDGE('',*,*,#651,.F.);
#653=ORIENTED_EDGE('',*,*,#73,.T.);
#654=CARTESIAN_POINT('',(-11.199854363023,3.2998,-5.8773690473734));
#655=CARTESIAN_POINT('',(-11.7067775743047,3.8497129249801,-6.09472915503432));
#656=CARTESIAN_POINT('',(-12.2136375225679,4.39970272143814,-6.31204221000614));
#657=CARTESIAN_POINT('',(-13.227230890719,5.49983605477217,-6.74657421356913));
#658=CARTESIAN_POINT('',(-13.7339643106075,6.04997959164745,-6.96379316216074));
#659=CARTESIAN_POINT('',(-14.240634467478,6.60019999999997,-7.18096505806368));
#660=B_SPLINE_CURVE_WITH_KNOTS('',3,(#654,#655,#656,#657,#658,#659),.UNSPECIFIED.,.F.,.F.,(4,2,
4),(0.,2.33657585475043,4.67315169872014),.UNSPECIFIED.);
#661=CARTESIAN_POINT('',(-11.200038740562,3.3,-5.87744810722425));
#662=VERTEX_POINT('',#661);
#663=EDGE_CURVE('E378',#662,#66,#660,.T.);
#664=ORIENTED_EDGE('',*,*,#663,.F.);
#665=CARTESIAN_POINT('',(-10.690038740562,3.3,-6.76079401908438));
#666=VERTEX_POINT('',#665);
#667=EDGE_CURVE('E390',#666,#662,#379,.F.);
#668=ORIENTED_EDGE('',*,*,#667,.F.);
#669=CARTESIAN_POINT('',(-13.3392153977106,6.60019999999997,-8.74226868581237));
#670=CARTESIAN_POINT('',(-12.8978039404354,6.04997959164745,-8.41206540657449));
#671=CARTESIAN_POINT('',(-12.4563201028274,5.49983605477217,-8.08183086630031));
#672=CARTESIAN_POINT('',(-11.573207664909,4.39970272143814,-7.42129926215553));
#673=CARTESIAN_POINT('',(-11.1315790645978,3.8497129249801,-7.09100219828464));
#674=CARTESIAN_POINT('',(-10.6898780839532,3.2998,-6.76067387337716));
#675=B_SPLINE_CURVE_WITH_KNOTS('',3,(#669,#670,#671,#672,#673,#674),.UNSPECIFIED.,.F.,.F.,(4,2,
4),(0.,2.33657584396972,4.67315169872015),.UNSPECIFIED.);
#676=EDGE_CURVE('E802',#40,#666,#675,.T.);
#677=ORIENTED_EDGE('',*,*,#676,.F.);
#678=ORIENTED_EDGE('',*,*,#41,.T.);
#679=EDGE_LOOP('',(#374,#383,#394,#398,#409,#418,#427,#428,#439,#443,#452,#453,#464,#468,#477,
#478,#489,#493,#502,#503,#514,#518,#527,#528,#539,#543,#552,#553,#564,#568,#577,#578,#589,#593,
#602,#603,#614,#618,#627,#628,#639,#643,#652,#653,#664,#668,#677,#678));
#680=FACE_BOUND('',#679,.T.);
#681=ORIENTED_EDGE('',*,*,#343,.F.);
#682=EDGE_LOOP('',(#681));
#683=FACE_BOUND('',#682,.T.);
#684=ADVANCED_FACE('F372',(#680,#683),#363,.T.);
#685=DIRECTION('',(-0.500000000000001,0.,-0.866025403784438));
#686=VECTOR('',#685,1.);
#687=CARTESIAN_POINT('',(-5.75786052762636,6.59999999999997,-11.7756976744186));
#688=LINE('',#687,#686);
#689=CARTESIAN_POINT('',(-6.75590451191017,6.59999999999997,-13.5043605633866));
#690=VERTEX_POINT('',#689);
#691=EDGE_CURVE('E386',#690,#392,#688,.T.);
#692=ORIENTED_EDGE('',*,*,#691,.F.);
#693=CARTESIAN_POINT('',(-0.901395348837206,6.59999999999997,-15.0730715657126));
#694=VERTEX_POINT('',#693);
#695=EDGE_CURVE('E735',#690,#694,#55,.T.);
#696=ORIENTED_EDGE('',*,*,#695,.T.);
#697=DIRECTION('',(0.,0.,1.));
#698=VECTOR('',#697,1.);
#699=CARTESIAN_POINT('',(-0.901395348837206,6.59999999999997,-15.1));
#700=LINE('',#699,#698);
#701=EDGE_CURVE('E719',#396,#694,#700,.T.);
#702=ORIENTED_EDGE('',*,*,#701,.F.);
#703=ORIENTED_EDGE('',*,*,#397,.F.);
#704=EDGE_LOOP('',(#692,#696,#702,#703));
#705=FACE_BOUND('',#704,.T.);
#706=ADVANCED_FACE('F507',(#705),#23,.T.);
#707=CARTESIAN_POINT('',(0.,6.59999999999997,0.));
#708=DIRECTION('',(0.,1.,0.));
#709=DIRECTION('',(0.,0.,1.));
#710=AXIS2_PLACEMENT_3D('',#707,#708,#709);
#711=CONICAL_SURFACE('',#710,15.1,0.78539816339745);
#712=CARTESIAN_POINT('',(-8.31728706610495,6.60019999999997,-12.6031256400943));
#713=CARTESIAN_POINT('',(-7.98713994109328,6.0499839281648,-12.1618104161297));
#714=CARTESIAN_POINT('',(-7.65696242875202,5.49984255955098,-11.7204248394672));
#715=CARTESIAN_POINT('',(-6.99654662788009,4.39970922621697,-10.837512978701));
#716=CARTESIAN_POINT('',(-6.66630833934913,3.84971726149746,-10.3959866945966));
#717=CARTESIAN_POINT('',(-6.33603966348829,3.2998,-9.95439005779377));
#718=B_SPLINE_CURVE_WITH_KNOTS('',3,(#712,#713,#714,#715,#716,#717),.UNSPECIFIED.,.F.,.F.,(4,2,
4),(0.,2.33633162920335,4.6726632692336),.UNSPECIFIED.);
#719=CARTESIAN_POINT('',(-6.33615978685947,3.3,-9.95455067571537));
#720=VERTEX_POINT('',#719);
#721=EDGE_CURVE('E11',#31,#720,#718,.T.);
#722=ORIENTED_EDGE('',*,*,#721,.F.);
#723=ORIENTED_EDGE('',*,*,#56,.F.);
#724=CARTESIAN_POINT('',(-9.95439005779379,3.2998,-6.33603966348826));
#725=CARTESIAN_POINT('',(-10.3959866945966,3.84971726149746,-6.66630833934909));
#726=CARTESIAN_POINT('',(-10.8375129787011,4.39970922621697,-6.99654662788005));
#727=CARTESIAN_POINT('',(-11.7204248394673,5.49984255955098,-7.65696242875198));
#728=CARTESIAN_POINT('',(-12.1618104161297,6.0499839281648,-7.98713994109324));
#729=CARTESIAN_POINT('',(-12.6031256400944,6.60019999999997,-8.3172870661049));
#730=B_SPLINE_CURVE_WITH_KNOTS('',3,(#724,#725,#726,#727,#728,#729),.UNSPECIFIED.,.F.,.F.,(4,2,
4),(0.,2.33633164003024,4.6726632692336),.UNSPECIFIED.);
#731=CARTESIAN_POINT('',(-9.95455067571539,3.3,-6.33615978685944));
#732=VERTEX_POINT('',#731);
#733=EDGE_CURVE('E654',#732,#48,#730,.T.);
#734=ORIENTED_EDGE('',*,*,#733,.F.);
#735=CARTESIAN_POINT('',(0.,3.3,0.));
#736=DIRECTION('',(0.,-1.,0.));
#737=DIRECTION('',(0.,0.,-1.));
#738=AXIS2_PLACEMENT_3D('',#735,#736,#737);
#739=CIRCLE('',#738,11.8);
#740=CARTESIAN_POINT('',(-10.4645506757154,3.3,-5.45281387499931));
#741=VERTEX_POINT('',#740);
#742=EDGE_CURVE('E752',#741,#732,#739,.T.);
#743=ORIENTED_EDGE('',*,*,#742,.F.);
#744=CARTESIAN_POINT('',(-13.5045447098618,6.60019999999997,-6.75598343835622));
#745=CARTESIAN_POINT('',(-12.997971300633,6.0499839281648,-6.53886680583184));
#746=CARTESIAN_POINT('',(-12.4913363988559,5.49984255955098,-6.32170443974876));
#747=CARTESIAN_POINT('',(-11.477943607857,4.39970922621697,-5.88728823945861));
#748=CARTESIAN_POINT('',(-10.9711857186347,3.84971726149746,-5.67003440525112));
#749=CARTESIAN_POINT('',(-10.4643663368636,3.2998,-5.4527348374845));
#750=B_SPLINE_CURVE_WITH_KNOTS('',3,(#744,#745,#746,#747,#748,#749),.UNSPECIFIED.,.F.,.F.,(4,2,
4),(0.,2.33633162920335,4.6726632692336),.UNSPECIFIED.);
#751=EDGE_CURVE('E659',#68,#741,#750,.T.);
#752=ORIENTED_EDGE('',*,*,#751,.F.);
#753=ORIENTED_EDGE('',*,*,#83,.F.);
#754=CARTESIAN_POINT('',(-11.7887745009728,3.2998,-0.509976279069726));
#755=CARTESIAN_POINT('',(-12.3363427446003,3.84971726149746,-0.575199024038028));
#756=CARTESIAN_POINT('',(-12.8838348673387,4.39970922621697,-0.640430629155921));
#757=CARTESIAN_POINT('',(-13.9786668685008,5.49984255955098,-0.770911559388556));
#758=CARTESIAN_POINT('',(-14.5260067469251,6.0499839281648,-0.836160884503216));
#759=CARTESIAN_POINT('',(-15.0732705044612,6.60019999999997,-0.901419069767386));
#760=B_SPLINE_CURVE_WITH_KNOTS('',3,(#754,#755,#756,#757,#758,#759),.UNSPECIFIED.,.F.,.F.,(4,2,
4),(0.,2.33633164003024,4.6726632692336),.UNSPECIFIED.);
#761=CARTESIAN_POINT('',(-11.7889736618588,3.3,-0.509999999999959));
#762=VERTEX_POINT('',#761);
#763=EDGE_CURVE('E636',#762,#80,#760,.T.);
#764=ORIENTED_EDGE('',*,*,#763,.F.);
#765=CARTESIAN_POINT('',(-11.7889736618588,3.3,0.510000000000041));
#766=VERTEX_POINT('',#765);
#767=EDGE_CURVE('E782',#766,#762,#739,.T.);
#768=ORIENTED_EDGE('',*,*,#767,.F.);
#769=CARTESIAN_POINT('',(-15.0732705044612,6.60019999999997,0.901419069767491));
#770=CARTESIAN_POINT('',(-14.5260067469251,6.0499839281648,0.836160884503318));
#771=CARTESIAN_POINT('',(-13.9786668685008,5.49984255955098,0.770911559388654));
#772=CARTESIAN_POINT('',(-12.8838348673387,4.39970922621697,0.640430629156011));
#773=CARTESIAN_POINT('',(-12.3363427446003,3.84971726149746,0.575199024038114));
#774=CARTESIAN_POINT('',(-11.7887745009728,3.2998,0.509976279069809));
#775=B_SPLINE_CURVE_WITH_KNOTS('',3,(#769,#770,#771,#772,#773,#774),.UNSPECIFIED.,.F.,.F.,(4,2,
4),(0.,2.33633162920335,4.6726632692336),.UNSPECIFIED.);
#776=EDGE_CURVE('E641',#95,#766,#775,.T.);
#777=ORIENTED_EDGE('',*,*,#776,.F.);
#778=ORIENTED_EDGE('',*,*,#110,.F.);
#779=CARTESIAN_POINT('',(-10.4643663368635,3.2998,5.45273483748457));
#780=CARTESIAN_POINT('',(-10.9711857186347,3.84971726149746,5.67003440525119));
#781=CARTESIAN_POINT('',(-11.477943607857,4.39970922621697,5.88728823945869));
#782=CARTESIAN_POINT('',(-12.4913363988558,5.49984255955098,6.32170443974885));
#783=CARTESIAN_POINT('',(-12.9979713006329,6.0499839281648,6.53886680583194));
#784=CARTESIAN_POINT('',(-13.5045447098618,6.60019999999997,6.75598343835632));
#785=B_SPLINE_CURVE_WITH_KNOTS('',3,(#779,#780,#781,#782,#783,#784),.UNSPECIFIED.,.F.,.F.,(4,2,
4),(0.,2.33633164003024,4.6726632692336),.UNSPECIFIED.);
#786=CARTESIAN_POINT('',(-10.4645506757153,3.3,5.45281387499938));
#787=VERTEX_POINT('',#786);
#788=EDGE_CURVE('E619',#787,#107,#785,.T.);
#789=ORIENTED_EDGE('',*,*,#788,.F.);
#790=CARTESIAN_POINT('',(-9.95455067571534,3.3,6.33615978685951));
#791=VERTEX_POINT('',#790);
#792=EDGE_CURVE('E780',#791,#787,#739,.T.);
#793=ORIENTED_EDGE('',*,*,#792,.F.);
#794=CARTESIAN_POINT('',(-12.6031256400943,6.60019999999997,8.31728706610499));
#795=CARTESIAN_POINT('',(-12.1618104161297,6.0499839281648,7.98713994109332));
#796=CARTESIAN_POINT('',(-11.7204248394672,5.49984255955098,7.65696242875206));
#797=CARTESIAN_POINT('',(-10.837512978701,4.39970922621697,6.99654662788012));
#798=CARTESIAN_POINT('',(-10.3959866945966,3.84971726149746,6.66630833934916));
#799=CARTESIAN_POINT('',(-9.95439005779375,3.2998,6.33603966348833));
#800=B_SPLINE_CURVE_WITH_KNOTS('',3,(#794,#795,#796,#797,#798,#799),.UNSPECIFIED.,.F.,.F.,(4,2,
4),(0.,2.33633162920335,4.6726632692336),.UNSPECIFIED.);
#801=EDGE_CURVE('E628',#122,#791,#800,.T.);
#802=ORIENTED_EDGE('',*,*,#801,.F.);
#803=ORIENTED_EDGE('',*,*,#137,.F.);
#804=CARTESIAN_POINT('',(-6.33603966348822,3.2998,9.95439005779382));
#805=CARTESIAN_POINT('',(-6.66630833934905,3.84971726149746,10.3959866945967));
#806=CARTESIAN_POINT('',(-6.99654662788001,4.39970922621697,10.8375129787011));
#807=CARTESIAN_POINT('',(-7.65696242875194,5.49984255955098,11.7204248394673));
#808=CARTESIAN_POINT('',(-7.9871399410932,6.0499839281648,12.1618104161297));
#809=CARTESIAN_POINT('',(-8.31728706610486,6.60019999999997,12.6031256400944));
#810=B_SPLINE_CURVE_WITH_KNOTS('',3,(#804,#805,#806,#807,#808,#809),.UNSPECIFIED.,.F.,.F.,(4,2,
4),(0.,2.33633164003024,4.6726632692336),.UNSPECIFIED.);
#811=CARTESIAN_POINT('',(-6.3361597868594,3.3,9.95455067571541));
#812=VERTEX_POINT('',#811);
#813=EDGE_CURVE('E603',#812,#134,#810,.T.);
#814=ORIENTED_EDGE('',*,*,#813,.F.);
#815=CARTESIAN_POINT('',(-5.45281387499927,3.3,10.4645506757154));
#816=VERTEX_POINT('',#815);
#817=EDGE_CURVE('E774',#816,#812,#739,.T.);
#818=ORIENTED_EDGE('',*,*,#817,.F.);
#819=CARTESIAN_POINT('',(-6.75598343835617,6.60019999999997,13.5045447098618));
#820=CARTESIAN_POINT('',(-6.5388668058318,6.0499839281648,12.997971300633));
#821=CARTESIAN_POINT('',(-6.32170443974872,5.49984255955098,12.4913363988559));
#822=CARTESIAN_POINT('',(-5.88728823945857,4.39970922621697,11.4779436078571));
#823=CARTESIAN_POINT('',(-5.67003440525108,3.84971726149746,10.9711857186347));
#824=CARTESIAN_POINT('',(-5.45273483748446,3.2998,10.4643663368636));
#825=B_SPLINE_CURVE_WITH_KNOTS('',3,(#819,#820,#821,#822,#823,#824),.UNSPECIFIED.,.F.,.F.,(4,2,
4),(0.,2.33633162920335,4.6726632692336),.UNSPECIFIED.);
#826=EDGE_CURVE('E615',#149,#816,#825,.T.);
#827=ORIENTED_EDGE('',*,*,#826,.F.);
#828=ORIENTED_EDGE('',*,*,#164,.F.);
#829=CARTESIAN_POINT('',(-0.509976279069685,3.2998,11.7887745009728));
#830=CARTESIAN_POINT('',(-0.575199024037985,3.84971726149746,12.3363427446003));
#831=CARTESIAN_POINT('',(-0.640430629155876,4.39970922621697,12.8838348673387));
#832=CARTESIAN_POINT('',(-0.770911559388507,5.49984255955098,13.9786668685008));
#833=CARTESIAN_POINT('',(-0.836160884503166,6.0499839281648,14.5260067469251));
#834=CARTESIAN_POINT('',(-0.901419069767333,6.60019999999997,15.0732705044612));
#835=B_SPLINE_CURVE_WITH_KNOTS('',3,(#829,#830,#831,#832,#833,#834),.UNSPECIFIED.,.F.,.F.,(4,2,
4),(0.,2.33633164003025,4.6726632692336),.UNSPECIFIED.);
#836=CARTESIAN_POINT('',(-0.509999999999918,3.3,11.7889736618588));
#837=VERTEX_POINT('',#836);
#838=EDGE_CURVE('E590',#837,#161,#835,.T.);
#839=ORIENTED_EDGE('',*,*,#838,.F.);
#840=CARTESIAN_POINT('',(0.510000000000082,3.3,11.7889736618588));
#841=VERTEX_POINT('',#840);
#842=EDGE_CURVE('E768',#841,#837,#739,.T.);
#843=ORIENTED_EDGE('',*,*,#842,.F.);
#844=CARTESIAN_POINT('',(0.901419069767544,6.60019999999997,15.0732705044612));
#845=CARTESIAN_POINT('',(0.836160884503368,6.0499839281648,14.5260067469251));
#846=CARTESIAN_POINT('',(0.770911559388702,5.49984255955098,13.9786668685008));
#847=CARTESIAN_POINT('',(0.640430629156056,4.39970922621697,12.8838348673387));
#848=CARTESIAN_POINT('',(0.575199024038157,3.84971726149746,12.3363427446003));
#849=CARTESIAN_POINT('',(0.50997627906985,3.2998,11.7887745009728));
#850=B_SPLINE_CURVE_WITH_KNOTS('',3,(#844,#845,#846,#847,#848,#849),.UNSPECIFIED.,.F.,.F.,(4,2,
4),(0.,2.33633162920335,4.6726632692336),.UNSPECIFIED.);
#851=EDGE_CURVE('E597',#176,#841,#850,.T.);
#852=ORIENTED_EDGE('',*,*,#851,.F.);
#853=ORIENTED_EDGE('',*,*,#191,.F.);
#854=CARTESIAN_POINT('',(5.4527348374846,3.2998,10.4643663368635));
#855=CARTESIAN_POINT('',(5.67003440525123,3.84971726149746,10.9711857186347));
#856=CARTESIAN_POINT('',(5.88728823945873,4.39970922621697,11.477943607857));
#857=CARTESIAN_POINT('',(6.32170443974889,5.49984255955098,12.4913363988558));
#858=CARTESIAN_POINT('',(6.53886680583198,6.0499839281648,12.9979713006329));
#859=CARTESIAN_POINT('',(6.75598343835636,6.60019999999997,13.5045447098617));
#860=B_SPLINE_CURVE_WITH_KNOTS('',3,(#854,#855,#856,#857,#858,#859),.UNSPECIFIED.,.F.,.F.,(4,2,
4),(0.,2.33633164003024,4.6726632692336),.UNSPECIFIED.);
#861=CARTESIAN_POINT('',(5.45281387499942,3.3,10.4645506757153));
#862=VERTEX_POINT('',#861);
#863=EDGE_CURVE('E575',#862,#188,#860,.T.);
#864=ORIENTED_EDGE('',*,*,#863,.F.);
#865=CARTESIAN_POINT('',(6.33615978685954,3.3,9.95455067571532));
#866=VERTEX_POINT('',#865);
#867=EDGE_CURVE('E764',#866,#862,#739,.T.);
#868=ORIENTED_EDGE('',*,*,#867,.F.);
#869=CARTESIAN_POINT('',(8.31728706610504,6.60019999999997,12.6031256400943));
#870=CARTESIAN_POINT('',(7.98713994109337,6.0499839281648,12.1618104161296));
#871=CARTESIAN_POINT('',(7.6569624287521,5.49984255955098,11.7204248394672));
#872=CARTESIAN_POINT('',(6.99654662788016,4.39970922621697,10.837512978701));
#873=CARTESIAN_POINT('',(6.6663083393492,3.84971726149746,10.3959866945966));
#874=CARTESIAN_POINT('',(6.33603966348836,3.2998,9.95439005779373));
#875=B_SPLINE_CURVE_WITH_KNOTS('',3,(#869,#870,#871,#872,#873,#874),.UNSPECIFIED.,.F.,.F.,(4,2,
4),(0.,2.33633162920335,4.6726632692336),.UNSPECIFIED.);
#876=EDGE_CURVE('E578',#203,#866,#875,.T.);
#877=ORIENTED_EDGE('',*,*,#876,.F.);
#878=ORIENTED_EDGE('',*,*,#218,.F.);
#879=CARTESIAN_POINT('',(9.95439005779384,3.2998,6.33603966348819));
#880=CARTESIAN_POINT('',(10.3959866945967,3.84971726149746,6.66630833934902));
#881=CARTESIAN_POINT('',(10.8375129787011,4.39970922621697,6.99654662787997));
#882=CARTESIAN_POINT('',(11.7204248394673,5.49984255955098,7.6569624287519));
#883=CARTESIAN_POINT('',(12.1618104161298,6.0499839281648,7.98713994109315));
#884=CARTESIAN_POINT('',(12.6031256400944,6.60019999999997,8.31728706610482));
#885=B_SPLINE_CURVE_WITH_KNOTS('',3,(#879,#880,#881,#882,#883,#884),.UNSPECIFIED.,.F.,.F.,(4,2,
4),(0.,2.33633164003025,4.6726632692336),.UNSPECIFIED.);
#886=CARTESIAN_POINT('',(9.95455067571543,3.3,6.33615978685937));
#887=VERTEX_POINT('',#886);
#888=EDGE_CURVE('E489',#887,#215,#885,.T.);
#889=ORIENTED_EDGE('',*,*,#888,.F.);
#890=CARTESIAN_POINT('',(10.4645506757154,3.3,5.45281387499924));
#891=VERTEX_POINT('',#890);
#892=EDGE_CURVE('E765',#891,#887,#739,.T.);
#893=ORIENTED_EDGE('',*,*,#892,.F.);
#894=CARTESIAN_POINT('',(13.5045447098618,6.60019999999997,6.75598343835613));
#895=CARTESIAN_POINT('',(12.997971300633,6.0499839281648,6.53886680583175));
#896=CARTESIAN_POINT('',(12.4913363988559,5.49984255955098,6.32170443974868));
#897=CARTESIAN_POINT('',(11.4779436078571,4.39970922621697,5.88728823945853));
#898=CARTESIAN_POINT('',(10.9711857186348,3.84971726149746,5.67003440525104));
#899=CARTESIAN_POINT('',(10.4643663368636,3.2998,5.45273483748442));
#900=B_SPLINE_CURVE_WITH_KNOTS('',3,(#894,#895,#896,#897,#898,#899),.UNSPECIFIED.,.F.,.F.,(4,2,
4),(0.,2.33633162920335,4.6726632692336),.UNSPECIFIED.);
#901=EDGE_CURVE('E564',#230,#891,#900,.T.);
#902=ORIENTED_EDGE('',*,*,#901,.F.);
#903=ORIENTED_EDGE('',*,*,#245,.F.);
#904=CARTESIAN_POINT('',(11.7887745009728,3.2998,0.509976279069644));
#905=CARTESIAN_POINT('',(12.3363427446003,3.84971726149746,0.575199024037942));
#906=CARTESIAN_POINT('',(12.8838348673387,4.39970922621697,0.640430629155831));
#907=CARTESIAN_POINT('',(13.9786668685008,5.49984255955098,0.770911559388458));
#908=CARTESIAN_POINT('',(14.5260067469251,6.0499839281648,0.836160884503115));
#909=CARTESIAN_POINT('',(15.0732705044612,6.60019999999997,0.901419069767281));
#910=B_SPLINE_CURVE_WITH_KNOTS('',3,(#904,#905,#906,#907,#908,#909),.UNSPECIFIED.,.F.,.F.,(4,2,
4),(0.,2.33633164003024,4.6726632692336),.UNSPECIFIED.);
#911=CARTESIAN_POINT('',(11.7889736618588,3.3,0.509999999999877));
#912=VERTEX_POINT('',#911);
#913=EDGE_CURVE('E495',#912,#242,#910,.T.);
#914=ORIENTED_EDGE('',*,*,#913,.F.);
#915=CARTESIAN_POINT('',(11.7889736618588,3.3,-0.510000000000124));
#916=VERTEX_POINT('',#915);
#917=EDGE_CURVE('E493',#916,#912,#739,.T.);
#918=ORIENTED_EDGE('',*,*,#917,.F.);
#919=CARTESIAN_POINT('',(15.0732705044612,6.60019999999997,-0.901419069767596));
#920=CARTESIAN_POINT('',(14.5260067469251,6.0499839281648,-0.836160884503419));
#921=CARTESIAN_POINT('',(13.9786668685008,5.49984255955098,-0.770911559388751));
#922=CARTESIAN_POINT('',(12.8838348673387,4.39970922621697,-0.640430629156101));
#923=CARTESIAN_POINT('',(12.3363427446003,3.84971726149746,-0.5751990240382));
#924=CARTESIAN_POINT('',(11.7887745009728,3.2998,-0.509976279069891));
#925=B_SPLINE_CURVE_WITH_KNOTS('',3,(#919,#920,#921,#922,#923,#924),.UNSPECIFIED.,.F.,.F.,(4,2,
4),(0.,2.33633162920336,4.6726632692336),.UNSPECIFIED.);
#926=EDGE_CURVE('E449',#257,#916,#925,.T.);
#927=ORIENTED_EDGE('',*,*,#926,.F.);
#928=ORIENTED_EDGE('',*,*,#272,.F.);
#929=CARTESIAN_POINT('',(10.4643663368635,3.2998,-5.45273483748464));
#930=CARTESIAN_POINT('',(10.9711857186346,3.84971726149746,-5.67003440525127));
#931=CARTESIAN_POINT('',(11.477943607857,4.39970922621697,-5.88728823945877));
#932=CARTESIAN_POINT('',(12.4913363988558,5.49984255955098,-6.32170443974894));
#933=CARTESIAN_POINT('',(12.9979713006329,6.0499839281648,-6.53886680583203));
#934=CARTESIAN_POINT('',(13.5045447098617,6.60019999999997,-6.75598343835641));
#935=B_SPLINE_CURVE_WITH_KNOTS('',3,(#929,#930,#931,#932,#933,#934),.UNSPECIFIED.,.F.,.F.,(4,2,
4),(0.,2.33633164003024,4.6726632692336),.UNSPECIFIED.);
#936=CARTESIAN_POINT('',(10.4645506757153,3.3,-5.45281387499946));
#937=VERTEX_POINT('',#936);
#938=EDGE_CURVE('E549',#937,#269,#935,.T.);
#939=ORIENTED_EDGE('',*,*,#938,.F.);
#940=CARTESIAN_POINT('',(9.9545506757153,3.3,-6.33615978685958));
#941=VERTEX_POINT('',#940);
#942=EDGE_CURVE('E754',#941,#937,#739,.T.);
#943=ORIENTED_EDGE('',*,*,#942,.F.);
#944=CARTESIAN_POINT('',(12.6031256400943,6.60019999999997,-8.31728706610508));
#945=CARTESIAN_POINT('',(12.1618104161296,6.0499839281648,-7.98713994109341));
#946=CARTESIAN_POINT('',(11.7204248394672,5.49984255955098,-7.65696242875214));
#947=CARTESIAN_POINT('',(10.837512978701,4.39970922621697,-6.9965466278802));
#948=CARTESIAN_POINT('',(10.3959866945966,3.84971726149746,-6.66630833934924));
#949=CARTESIAN_POINT('',(9.95439005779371,3.2998,-6.3360396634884));
#950=B_SPLINE_CURVE_WITH_KNOTS('',3,(#944,#945,#946,#947,#948,#949),.UNSPECIFIED.,.F.,.F.,(4,2,
4),(0.,2.33633162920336,4.6726632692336),.UNSPECIFIED.);
#951=EDGE_CURVE('E558',#284,#941,#950,.T.);
#952=ORIENTED_EDGE('',*,*,#951,.F.);
#953=ORIENTED_EDGE('',*,*,#299,.F.);
#954=CARTESIAN_POINT('',(6.33603966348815,3.2998,-9.95439005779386));
#955=CARTESIAN_POINT('',(6.66630833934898,3.84971726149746,-10.3959866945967));
#956=CARTESIAN_POINT('',(6.99654662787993,4.39970922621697,-10.8375129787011));
#957=CARTESIAN_POINT('',(7.65696242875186,5.49984255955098,-11.7204248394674));
#958=CARTESIAN_POINT('',(7.98713994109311,6.0499839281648,-12.1618104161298));
#959=CARTESIAN_POINT('',(8.31728706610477,6.60019999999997,-12.6031256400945));
#960=B_SPLINE_CURVE_WITH_KNOTS('',3,(#954,#955,#956,#957,#958,#959),.UNSPECIFIED.,.F.,.F.,(4,2,
4),(0.,2.33633164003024,4.6726632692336),.UNSPECIFIED.);
#961=CARTESIAN_POINT('',(6.33615978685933,3.3,-9.95455067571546));
#962=VERTEX_POINT('',#961);
#963=EDGE_CURVE('E535',#962,#296,#960,.T.);
#964=ORIENTED_EDGE('',*,*,#963,.F.);
#965=CARTESIAN_POINT('',(5.4528138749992,3.3,-10.4645506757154));
#966=VERTEX_POINT('',#965);
#967=EDGE_CURVE('E370',#966,#962,#739,.T.);
#968=ORIENTED_EDGE('',*,*,#967,.F.);
#969=CARTESIAN_POINT('',(6.75598343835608,6.60019999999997,-13.5045447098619));
#970=CARTESIAN_POINT('',(6.53886680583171,6.0499839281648,-12.997971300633));
#971=CARTESIAN_POINT('',(6.32170443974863,5.49984255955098,-12.4913363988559));
#972=CARTESIAN_POINT('',(5.88728823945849,4.39970922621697,-11.4779436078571));
#973=CARTESIAN_POINT('',(5.670034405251,3.84971726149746,-10.9711857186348));
#974=CARTESIAN_POINT('',(5.45273483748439,3.2998,-10.4643663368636));
#975=B_SPLINE_CURVE_WITH_KNOTS('',3,(#969,#970,#971,#972,#973,#974),.UNSPECIFIED.,.F.,.F.,(4,2,
4),(0.,2.33633162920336,4.6726632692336),.UNSPECIFIED.);
#976=EDGE_CURVE('E542',#311,#966,#975,.T.);
#977=ORIENTED_EDGE('',*,*,#976,.F.);
#978=ORIENTED_EDGE('',*,*,#326,.F.);
#979=CARTESIAN_POINT('',(0.509976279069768,3.2998,-11.7887745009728));
#980=CARTESIAN_POINT('',(0.575199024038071,3.84971726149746,-12.3363427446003));
#981=CARTESIAN_POINT('',(0.640430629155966,4.39970922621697,-12.8838348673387));
#982=CARTESIAN_POINT('',(0.770911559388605,5.49984255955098,-13.9786668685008));
#983=CARTESIAN_POINT('',(0.836160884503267,6.0499839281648,-14.5260067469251));
#984=CARTESIAN_POINT('',(0.901419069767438,6.60019999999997,-15.0732705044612));
#985=B_SPLINE_CURVE_WITH_KNOTS('',3,(#979,#980,#981,#982,#983,#984),.UNSPECIFIED.,.F.,.F.,(4,2,
4),(0.,2.33633164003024,4.6726632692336),.UNSPECIFIED.);
#986=CARTESIAN_POINT('',(0.51,3.3,-11.7889736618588));
#987=VERTEX_POINT('',#986);
#988=EDGE_CURVE('E513',#987,#323,#985,.T.);
#989=ORIENTED_EDGE('',*,*,#988,.F.);
#990=CARTESIAN_POINT('',(0.,3.3,0.));
#991=DIRECTION('',(0.,-1.,0.));
#992=DIRECTION('',(0.,0.,-1.));
#993=AXIS2_PLACEMENT_3D('',#990,#991,#992);
#994=CIRCLE('',#993,11.8);
#995=CARTESIAN_POINT('',(-0.51,3.3,-11.7889736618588));
#996=VERTEX_POINT('',#995);
#997=EDGE_CURVE('E743',#996,#987,#994,.T.);
#998=ORIENTED_EDGE('',*,*,#997,.F.);
#999=CARTESIAN_POINT('',(-0.901419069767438,6.60019999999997,-15.0732705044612));
#1000=CARTESIAN_POINT('',(-0.836160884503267,6.0499839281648,-14.5260067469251));
#1001=CARTESIAN_POINT('',(-0.770911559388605,5.49984255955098,-13.9786668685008));
#1002=CARTESIAN_POINT('',(-0.640430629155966,4.39970922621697,-12.8838348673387));
#1003=CARTESIAN_POINT('',(-0.575199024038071,3.84971726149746,-12.3363427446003));
#1004=CARTESIAN_POINT('',(-0.509976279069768,3.2998,-11.7887745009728));
#1005=B_SPLINE_CURVE_WITH_KNOTS('',3,(#999,#1000,#1001,#1002,#1003,#1004),.UNSPECIFIED.,.F.,.F.,
(4,2,4),(0.,2.33633162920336,4.6726632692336),.UNSPECIFIED.);
#1006=EDGE_CURVE('E523',#694,#996,#1005,.T.);
#1007=ORIENTED_EDGE('',*,*,#1006,.F.);
#1008=ORIENTED_EDGE('',*,*,#695,.F.);
#1009=CARTESIAN_POINT('',(-5.45273483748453,3.2998,-10.4643663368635));
#1010=CARTESIAN_POINT('',(-5.67003440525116,3.84971726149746,-10.9711857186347));
#1011=CARTESIAN_POINT('',(-5.88728823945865,4.39970922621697,-11.477943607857));
#1012=CARTESIAN_POINT('',(-6.32170443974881,5.49984255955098,-12.4913363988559));
#1013=CARTESIAN_POINT('',(-6.53886680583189,6.0499839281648,-12.997971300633));
#1014=CARTESIAN_POINT('',(-6.75598343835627,6.60019999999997,-13.5045447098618));
#1015=B_SPLINE_CURVE_WITH_KNOTS('',3,(#1009,#1010,#1011,#1012,#1013,#1014),.UNSPECIFIED.,.F.,
.F.,(4,2,4),(0.,2.33633164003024,4.6726632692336),.UNSPECIFIED.);
#1016=CARTESIAN_POINT('',(-5.45281387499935,3.3,-10.4645506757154));
#1017=VERTEX_POINT('',#1016);
#1018=EDGE_CURVE('E52',#1017,#690,#1015,.T.);
#1019=ORIENTED_EDGE('',*,*,#1018,.F.);
#1020=EDGE_CURVE('E669',#720,#1017,#739,.T.);
#1021=ORIENTED_EDGE('',*,*,#1020,.F.);
#1022=EDGE_LOOP('',(#722,#723,#734,#743,#752,#753,#764,#768,#777,#778,#789,#793,#802,#803,#814,
#818,#827,#828,#839,#843,#852,#853,#864,#868,#877,#878,#889,#893,#902,#903,#914,#918,#927,#928,
#939,#943,#952,#953,#964,#968,#977,#978,#989,#998,#1007,#1008,#1019,#1021));
#1023=FACE_BOUND('',#1022,.T.);
#1024=ORIENTED_EDGE('',*,*,#354,.T.);
#1025=EDGE_LOOP('',(#1024));
#1026=FACE_BOUND('',#1025,.T.);
#1027=ADVANCED_FACE('F503',(#1023,#1026),#711,.F.);
#1028=CARTESIAN_POINT('',(-0.51,3.3,-15.9485281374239));
#1029=DIRECTION('',(-0.993039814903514,-0.117779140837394,0.));
#1030=DIRECTION('',(0.117779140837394,-0.993039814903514,0.));
#1031=AXIS2_PLACEMENT_3D('',#1028,#1029,#1030);
#1032=PLANE('',#1031);
#1033=ORIENTED_EDGE('',*,*,#408,.T.);
#1034=ORIENTED_EDGE('',*,*,#701,.T.);
#1035=ORIENTED_EDGE('',*,*,#1006,.T.);
#1036=DIRECTION('',(0.,0.,1.));
#1037=VECTOR('',#1036,1.);
#1038=CARTESIAN_POINT('',(-0.51,3.3,-15.9485281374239));
#1039=LINE('',#1038,#1037);
#1040=EDGE_CURVE('E694',#407,#996,#1039,.T.);
#1041=ORIENTED_EDGE('',*,*,#1040,.F.);
#1042=EDGE_LOOP('',(#1033,#1034,#1035,#1041));
#1043=FACE_BOUND('',#1042,.T.);
#1044=ADVANCED_FACE('F510',(#1043),#1032,.F.);
#1045=CARTESIAN_POINT('',(0.51,3.3,-15.9485281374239));
#1046=DIRECTION('',(0.993039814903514,-0.117779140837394,0.));
#1047=DIRECTION('',(0.117779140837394,0.993039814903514,0.));
#1048=AXIS2_PLACEMENT_3D('',#1045,#1046,#1047);
#1049=PLANE('',#1048);
#1050=ORIENTED_EDGE('',*,*,#426,.T.);
#1051=DIRECTION('',(0.,0.,1.));
#1052=VECTOR('',#1051,1.);
#1053=CARTESIAN_POINT('',(0.51,3.3,-15.9485281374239));
#1054=LINE('',#1053,#1052);
#1055=EDGE_CURVE('E696',#416,#987,#1054,.T.);
#1056=ORIENTED_EDGE('',*,*,#1055,.T.);
#1057=ORIENTED_EDGE('',*,*,#988,.T.);
#1058=ORIENTED_EDGE('',*,*,#324,.T.);
#1059=EDGE_LOOP('',(#1050,#1056,#1057,#1058));
#1060=FACE_BOUND('',#1059,.T.);
#1061=ADVANCED_FACE('F705',(#1060),#1049,.F.);
#1062=CARTESIAN_POINT('',(-0.51,3.3,-15.9485281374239));
#1063=DIRECTION('',(0.,-1.,0.));
#1064=DIRECTION('',(0.,0.,-1.));
#1065=AXIS2_PLACEMENT_3D('',#1062,#1063,#1064);
#1066=PLANE('',#1065);
#1067=ORIENTED_EDGE('',*,*,#417,.T.);
#1068=ORIENTED_EDGE('',*,*,#1040,.T.);
#1069=ORIENTED_EDGE('',*,*,#997,.T.);
#1070=ORIENTED_EDGE('',*,*,#1055,.F.);
#1071=EDGE_LOOP('',(#1067,#1068,#1069,#1070));
#1072=FACE_BOUND('',#1071,.T.);
#1073=ADVANCED_FACE('F707',(#1072),#1066,.F.);
#1074=CARTESIAN_POINT('',(10.4403353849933,3.3,-19.1031913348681));
#1075=DIRECTION('',(-0.859997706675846,-0.117779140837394,-0.496519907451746));
#1076=DIRECTION('',(-0.499999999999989,0.,0.866025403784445));
#1077=AXIS2_PLACEMENT_3D('',#1074,#1075,#1076);
#1078=PLANE('',#1077);
#1079=ORIENTED_EDGE('',*,*,#438,.T.);
#1080=ORIENTED_EDGE('',*,*,#312,.T.);
#1081=ORIENTED_EDGE('',*,*,#976,.T.);
#1082=DIRECTION('',(-0.499999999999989,0.,0.866025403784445));
#1083=VECTOR('',#1082,1.);
#1084=CARTESIAN_POINT('',(10.4403353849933,3.3,-19.1031913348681));
#1085=LINE('',#1084,#1083);
#1086=EDGE_CURVE('E369',#437,#966,#1085,.T.);
#1087=ORIENTED_EDGE('',*,*,#1086,.F.);
#1088=EDGE_LOOP('',(#1079,#1080,#1081,#1087));
#1089=FACE_BOUND('',#1088,.T.);
#1090=ADVANCED_FACE('F896',(#1089),#1078,.F.);
#1091=CARTESIAN_POINT('',(11.3236812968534,3.3,-18.5931913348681));
#1092=DIRECTION('',(0.859997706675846,-0.117779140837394,0.496519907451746));
#1093=DIRECTION('',(0.499999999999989,0.,-0.866025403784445));
#1094=AXIS2_PLACEMENT_3D('',#1091,#1092,#1093);
#1095=PLANE('',#1094);
#1096=ORIENTED_EDGE('',*,*,#451,.T.);
#1097=DIRECTION('',(-0.499999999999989,0.,0.866025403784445));
#1098=VECTOR('',#1097,1.);
#1099=CARTESIAN_POINT('',(11.3236812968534,3.3,-18.5931913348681));
#1100=LINE('',#1099,#1098);
#1101=EDGE_CURVE('E352',#441,#962,#1100,.T.);
#1102=ORIENTED_EDGE('',*,*,#1101,.T.);
#1103=ORIENTED_EDGE('',*,*,#963,.T.);
#1104=ORIENTED_EDGE('',*,*,#297,.T.);
#1105=EDGE_LOOP('',(#1096,#1102,#1103,#1104));
#1106=FACE_BOUND('',#1105,.T.);
#1107=ADVANCED_FACE('F348',(#1106),#1095,.F.);
#1108=CARTESIAN_POINT('',(-11.3236812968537,3.3,-18.593191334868));
#1109=DIRECTION('',(0.,-1.,0.));
#1110=DIRECTION('',(0.,0.,-1.));
#1111=AXIS2_PLACEMENT_3D('',#1108,#1109,#1110);
#1112=PLANE('',#1111);
#1113=ORIENTED_EDGE('',*,*,#442,.T.);
#1114=ORIENTED_EDGE('',*,*,#1086,.T.);
#1115=ORIENTED_EDGE('',*,*,#967,.T.);
#1116=ORIENTED_EDGE('',*,*,#1101,.F.);
#1117=EDGE_LOOP('',(#1113,#1114,#1115,#1116));
#1118=FACE_BOUND('',#1117,.T.);
#1119=ADVANCED_FACE('F365',(#1118),#1112,.F.);
#1120=CARTESIAN_POINT('',(18.6012724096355,3.3,-11.3283469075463));
#1121=DIRECTION('',(-0.496519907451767,-0.117779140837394,-0.859997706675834));
#1122=DIRECTION('',(-0.866025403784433,0.,0.50000000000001));
#1123=AXIS2_PLACEMENT_3D('',#1120,#1121,#1122);
#1124=PLANE('',#1123);
#1125=ORIENTED_EDGE('',*,*,#463,.T.);
#1126=ORIENTED_EDGE('',*,*,#285,.T.);
#1127=ORIENTED_EDGE('',*,*,#951,.T.);
#1128=DIRECTION('',(-0.866025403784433,0.,0.50000000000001));
#1129=VECTOR('',#1128,1.);
#1130=CARTESIAN_POINT('',(18.6012724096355,3.3,-11.3283469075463));
#1131=LINE('',#1130,#1129);
#1132=EDGE_CURVE('E367',#462,#941,#1131,.T.);
#1133=ORIENTED_EDGE('',*,*,#1132,.F.);
#1134=EDGE_LOOP('',(#1125,#1126,#1127,#1133));
#1135=FACE_BOUND('',#1134,.T.);
#1136=ADVANCED_FACE('F888',(#1135),#1124,.F.);
#1137=CARTESIAN_POINT('',(19.1112724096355,3.3,-10.4450009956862));
#1138=DIRECTION('',(0.496519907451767,-0.117779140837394,0.859997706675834));
#1139=DIRECTION('',(0.866025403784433,0.,-0.50000000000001));
#1140=AXIS2_PLACEMENT_3D('',#1137,#1138,#1139);
#1141=PLANE('',#1140);
#1142=ORIENTED_EDGE('',*,*,#476,.T.);
#1143=DIRECTION('',(-0.866025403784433,0.,0.50000000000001));
#1144=VECTOR('',#1143,1.);
#1145=CARTESIAN_POINT('',(19.1112724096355,3.3,-10.4450009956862));
#1146=LINE('',#1145,#1144);
#1147=EDGE_CURVE('E446',#466,#937,#1146,.T.);
#1148=ORIENTED_EDGE('',*,*,#1147,.T.);
#1149=ORIENTED_EDGE('',*,*,#938,.T.);
#1150=ORIENTED_EDGE('',*,*,#270,.T.);
#1151=EDGE_LOOP('',(#1142,#1148,#1149,#1150));
#1152=FACE_BOUND('',#1151,.T.);
#1153=ADVANCED_FACE('F891',(#1152),#1141,.F.);
#1154=ORIENTED_EDGE('',*,*,#467,.T.);
#1155=ORIENTED_EDGE('',*,*,#1132,.T.);
#1156=ORIENTED_EDGE('',*,*,#942,.T.);
#1157=ORIENTED_EDGE('',*,*,#1147,.F.);
#1158=EDGE_LOOP('',(#1154,#1155,#1156,#1157));
#1159=FACE_BOUND('',#1158,.T.);
#1160=ADVANCED_FACE('F477',(#1159),#1112,.F.);
#1161=CARTESIAN_POINT('',(15.948528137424,3.3,-0.510000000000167));
#1162=DIRECTION('',(0.,-0.117779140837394,-0.993039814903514));
#1163=DIRECTION('',(0.,0.993039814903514,-0.117779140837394));
#1164=AXIS2_PLACEMENT_3D('',#1161,#1162,#1163);
#1165=PLANE('',#1164);
#1166=ORIENTED_EDGE('',*,*,#488,.T.);
#1167=ORIENTED_EDGE('',*,*,#258,.T.);
#1168=ORIENTED_EDGE('',*,*,#926,.T.);
#1169=DIRECTION('',(-1.,0.,0.));
#1170=VECTOR('',#1169,1.);
#1171=CARTESIAN_POINT('',(15.948528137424,3.3,-0.510000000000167));
#1172=LINE('',#1171,#1170);
#1173=EDGE_CURVE('E438',#487,#916,#1172,.T.);
#1174=ORIENTED_EDGE('',*,*,#1173,.F.);
#1175=EDGE_LOOP('',(#1166,#1167,#1168,#1174));
#1176=FACE_BOUND('',#1175,.T.);
#1177=ADVANCED_FACE('F443',(#1176),#1165,.F.);
#1178=CARTESIAN_POINT('',(15.948528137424,3.3,0.509999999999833));
#1179=DIRECTION('',(0.,-0.117779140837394,0.993039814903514));
#1180=DIRECTION('',(0.,-0.993039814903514,-0.117779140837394));
#1181=AXIS2_PLACEMENT_3D('',#1178,#1179,#1180);
#1182=PLANE('',#1181);
#1183=ORIENTED_EDGE('',*,*,#501,.T.);
#1184=DIRECTION('',(-1.,0.,0.));
#1185=VECTOR('',#1184,1.);
#1186=CARTESIAN_POINT('',(15.948528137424,3.3,0.509999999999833));
#1187=LINE('',#1186,#1185);
#1188=EDGE_CURVE('E439',#491,#912,#1187,.T.);
#1189=ORIENTED_EDGE('',*,*,#1188,.T.);
#1190=ORIENTED_EDGE('',*,*,#913,.T.);
#1191=ORIENTED_EDGE('',*,*,#243,.T.);
#1192=EDGE_LOOP('',(#1183,#1189,#1190,#1191));
#1193=FACE_BOUND('',#1192,.T.);
#1194=ADVANCED_FACE('F474',(#1193),#1182,.F.);
#1195=ORIENTED_EDGE('',*,*,#492,.T.);
#1196=ORIENTED_EDGE('',*,*,#1173,.T.);
#1197=ORIENTED_EDGE('',*,*,#917,.T.);
#1198=ORIENTED_EDGE('',*,*,#1188,.F.);
#1199=EDGE_LOOP('',(#1195,#1196,#1197,#1198));
#1200=FACE_BOUND('',#1199,.T.);
#1201=ADVANCED_FACE('F436',(#1200),#1112,.F.);
#1202=CARTESIAN_POINT('',(19.1223113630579,3.3,10.4513743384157));
#1203=DIRECTION('',(0.496519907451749,-0.117779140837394,-0.859997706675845));
#1204=DIRECTION('',(-0.866025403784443,0.,-0.499999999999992));
#1205=AXIS2_PLACEMENT_3D('',#1202,#1203,#1204);
#1206=PLANE('',#1205);
#1207=ORIENTED_EDGE('',*,*,#513,.T.);
#1208=ORIENTED_EDGE('',*,*,#231,.T.);
#1209=ORIENTED_EDGE('',*,*,#901,.T.);
#1210=DIRECTION('',(-0.866025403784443,0.,-0.499999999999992));
#1211=VECTOR('',#1210,1.);
#1212=CARTESIAN_POINT('',(19.1223113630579,3.3,10.4513743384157));
#1213=LINE('',#1212,#1211);
#1214=EDGE_CURVE('E1130',#512,#891,#1213,.T.);
#1215=ORIENTED_EDGE('',*,*,#1214,.F.);
#1216=EDGE_LOOP('',(#1207,#1208,#1209,#1215));
#1217=FACE_BOUND('',#1216,.T.);
#1218=ADVANCED_FACE('F945',(#1217),#1206,.F.);
#1219=CARTESIAN_POINT('',(18.6123113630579,3.3,11.3347202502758));
#1220=DIRECTION('',(-0.496519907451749,-0.117779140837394,0.859997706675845));
#1221=DIRECTION('',(0.866025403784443,0.,0.499999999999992));
#1222=AXIS2_PLACEMENT_3D('',#1219,#1220,#1221);
#1223=PLANE('',#1222);
#1224=ORIENTED_EDGE('',*,*,#526,.T.);
#1225=DIRECTION('',(-0.866025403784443,0.,-0.499999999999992));
#1226=VECTOR('',#1225,1.);
#1227=CARTESIAN_POINT('',(18.6123113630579,3.3,11.3347202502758));
#1228=LINE('',#1227,#1226);
#1229=EDGE_CURVE('E1123',#516,#887,#1228,.T.);
#1230=ORIENTED_EDGE('',*,*,#1229,.T.);
#1231=ORIENTED_EDGE('',*,*,#888,.T.);
#1232=ORIENTED_EDGE('',*,*,#216,.T.);
#1233=EDGE_LOOP('',(#1224,#1230,#1231,#1232));
#1234=FACE_BOUND('',#1233,.T.);
#1235=ADVANCED_FACE('F476',(#1234),#1223,.F.);
#1236=ORIENTED_EDGE('',*,*,#517,.T.);
#1237=ORIENTED_EDGE('',*,*,#1214,.T.);
#1238=ORIENTED_EDGE('',*,*,#892,.T.);
#1239=ORIENTED_EDGE('',*,*,#1229,.F.);
#1240=EDGE_LOOP('',(#1236,#1237,#1238,#1239));
#1241=FACE_BOUND('',#1240,.T.);
#1242=ADVANCED_FACE('F1212',(#1241),#1112,.F.);
#1243=CARTESIAN_POINT('',(11.3347202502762,3.3,18.6123113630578));
#1244=DIRECTION('',(0.859997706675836,-0.117779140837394,-0.496519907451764));
#1245=DIRECTION('',(-0.500000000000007,0.,-0.866025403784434));
#1246=AXIS2_PLACEMENT_3D('',#1243,#1244,#1245);
#1247=PLANE('',#1246);
#1248=ORIENTED_EDGE('',*,*,#538,.T.);
#1249=ORIENTED_EDGE('',*,*,#204,.T.);
#1250=ORIENTED_EDGE('',*,*,#876,.T.);
#1251=DIRECTION('',(-0.500000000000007,0.,-0.866025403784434));
#1252=VECTOR('',#1251,1.);
#1253=CARTESIAN_POINT('',(11.3347202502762,3.3,18.6123113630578));
#1254=LINE('',#1253,#1252);
#1255=EDGE_CURVE('E1125',#537,#866,#1254,.T.);
#1256=ORIENTED_EDGE('',*,*,#1255,.F.);
#1257=EDGE_LOOP('',(#1248,#1249,#1250,#1256));
#1258=FACE_BOUND('',#1257,.T.);
#1259=ADVANCED_FACE('F955',(#1258),#1247,.F.);
#1260=CARTESIAN_POINT('',(10.4513743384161,3.3,19.1223113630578));
#1261=DIRECTION('',(-0.859997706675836,-0.117779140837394,0.496519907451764));
#1262=DIRECTION('',(0.500000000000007,0.,0.866025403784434));
#1263=AXIS2_PLACEMENT_3D('',#1260,#1261,#1262);
#1264=PLANE('',#1263);
#1265=ORIENTED_EDGE('',*,*,#551,.T.);
#1266=DIRECTION('',(-0.500000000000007,0.,-0.866025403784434));
#1267=VECTOR('',#1266,1.);
#1268=CARTESIAN_POINT('',(10.4513743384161,3.3,19.1223113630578));
#1269=LINE('',#1268,#1267);
#1270=EDGE_CURVE('E1122',#541,#862,#1269,.T.);
#1271=ORIENTED_EDGE('',*,*,#1270,.T.);
#1272=ORIENTED_EDGE('',*,*,#863,.T.);
#1273=ORIENTED_EDGE('',*,*,#189,.T.);
#1274=EDGE_LOOP('',(#1265,#1271,#1272,#1273));
#1275=FACE_BOUND('',#1274,.T.);
#1276=ADVANCED_FACE('F950',(#1275),#1264,.F.);
#1277=ORIENTED_EDGE('',*,*,#542,.T.);
#1278=ORIENTED_EDGE('',*,*,#1255,.T.);
#1279=ORIENTED_EDGE('',*,*,#867,.T.);
#1280=ORIENTED_EDGE('',*,*,#1270,.F.);
#1281=EDGE_LOOP('',(#1277,#1278,#1279,#1280));
#1282=FACE_BOUND('',#1281,.T.);
#1283=ADVANCED_FACE('F951',(#1282),#1112,.F.);
#1284=CARTESIAN_POINT('',(0.510000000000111,3.3,15.948528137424));
#1285=DIRECTION('',(0.993039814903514,-0.117779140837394,0.));
#1286=DIRECTION('',(0.117779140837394,0.993039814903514,0.));
#1287=AXIS2_PLACEMENT_3D('',#1284,#1285,#1286);
#1288=PLANE('',#1287);
#1289=ORIENTED_EDGE('',*,*,#563,.T.);
#1290=ORIENTED_EDGE('',*,*,#177,.T.);
#1291=ORIENTED_EDGE('',*,*,#851,.T.);
#1292=DIRECTION('',(0.,0.,-1.));
#1293=VECTOR('',#1292,1.);
#1294=CARTESIAN_POINT('',(0.510000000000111,3.3,15.948528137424));
#1295=LINE('',#1294,#1293);
#1296=EDGE_CURVE('E1127',#562,#841,#1295,.T.);
#1297=ORIENTED_EDGE('',*,*,#1296,.F.);
#1298=EDGE_LOOP('',(#1289,#1290,#1291,#1297));
#1299=FACE_BOUND('',#1298,.T.);
#1300=ADVANCED_FACE('F984',(#1299),#1288,.F.);
#1301=CARTESIAN_POINT('',(-0.509999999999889,3.3,15.948528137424));
#1302=DIRECTION('',(-0.993039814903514,-0.117779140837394,0.));
#1303=DIRECTION('',(0.117779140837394,-0.993039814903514,0.));
#1304=AXIS2_PLACEMENT_3D('',#1301,#1302,#1303);
#1305=PLANE('',#1304);
#1306=ORIENTED_EDGE('',*,*,#576,.T.);
#1307=DIRECTION('',(0.,0.,-1.));
#1308=VECTOR('',#1307,1.);
#1309=CARTESIAN_POINT('',(-0.509999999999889,3.3,15.948528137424));
#1310=LINE('',#1309,#1308);
#1311=EDGE_CURVE('E1135',#566,#837,#1310,.T.);
#1312=ORIENTED_EDGE('',*,*,#1311,.T.);
#1313=ORIENTED_EDGE('',*,*,#838,.T.);
#1314=ORIENTED_EDGE('',*,*,#162,.T.);
#1315=EDGE_LOOP('',(#1306,#1312,#1313,#1314));
#1316=FACE_BOUND('',#1315,.T.);
#1317=ADVANCED_FACE('F978',(#1316),#1305,.F.);
#1318=ORIENTED_EDGE('',*,*,#567,.T.);
#1319=ORIENTED_EDGE('',*,*,#1296,.T.);
#1320=ORIENTED_EDGE('',*,*,#842,.T.);
#1321=ORIENTED_EDGE('',*,*,#1311,.F.);
#1322=EDGE_LOOP('',(#1318,#1319,#1320,#1321));
#1323=FACE_BOUND('',#1322,.T.);
#1324=ADVANCED_FACE('F983',(#1323),#1112,.F.);
#1325=CARTESIAN_POINT('',(-10.4513743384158,3.3,19.1223113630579));
#1326=DIRECTION('',(0.859997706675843,-0.117779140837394,0.496519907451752));
#1327=DIRECTION('',(0.499999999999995,0.,-0.866025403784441));
#1328=AXIS2_PLACEMENT_3D('',#1325,#1326,#1327);
#1329=PLANE('',#1328);
#1330=ORIENTED_EDGE('',*,*,#588,.T.);
#1331=ORIENTED_EDGE('',*,*,#150,.T.);
#1332=ORIENTED_EDGE('',*,*,#826,.T.);
#1333=DIRECTION('',(0.499999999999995,0.,-0.866025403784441));
#1334=VECTOR('',#1333,1.);
#1335=CARTESIAN_POINT('',(-10.4513743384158,3.3,19.1223113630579));
#1336=LINE('',#1335,#1334);
#1337=EDGE_CURVE('E1134',#587,#816,#1336,.T.);
#1338=ORIENTED_EDGE('',*,*,#1337,.F.);
#1339=EDGE_LOOP('',(#1330,#1331,#1332,#1338));
#1340=FACE_BOUND('',#1339,.T.);
#1341=ADVANCED_FACE('F1020',(#1340),#1329,.F.);
#1342=CARTESIAN_POINT('',(-11.3347202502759,3.3,18.6123113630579));
#1343=DIRECTION('',(-0.859997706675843,-0.117779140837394,-0.496519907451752));
#1344=DIRECTION('',(-0.499999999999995,0.,0.866025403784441));
#1345=AXIS2_PLACEMENT_3D('',#1342,#1343,#1344);
#1346=PLANE('',#1345);
#1347=ORIENTED_EDGE('',*,*,#601,.T.);
#1348=DIRECTION('',(0.499999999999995,0.,-0.866025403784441));
#1349=VECTOR('',#1348,1.);
#1350=CARTESIAN_POINT('',(-11.3347202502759,3.3,18.6123113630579));
#1351=LINE('',#1350,#1349);
#1352=EDGE_CURVE('E1138',#591,#812,#1351,.T.);
#1353=ORIENTED_EDGE('',*,*,#1352,.T.);
#1354=ORIENTED_EDGE('',*,*,#813,.T.);
#1355=ORIENTED_EDGE('',*,*,#135,.T.);
#1356=EDGE_LOOP('',(#1347,#1353,#1354,#1355));
#1357=FACE_BOUND('',#1356,.T.);
#1358=ADVANCED_FACE('F988',(#1357),#1346,.F.);
#1359=ORIENTED_EDGE('',*,*,#592,.T.);
#1360=ORIENTED_EDGE('',*,*,#1337,.T.);
#1361=ORIENTED_EDGE('',*,*,#817,.T.);
#1362=ORIENTED_EDGE('',*,*,#1352,.F.);
#1363=EDGE_LOOP('',(#1359,#1360,#1361,#1362));
#1364=FACE_BOUND('',#1363,.T.);
#1365=ADVANCED_FACE('F1203',(#1364),#1112,.F.);
#1366=CARTESIAN_POINT('',(-18.6123113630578,3.3,11.3347202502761));
#1367=DIRECTION('',(0.496519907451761,-0.117779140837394,0.859997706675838));
#1368=DIRECTION('',(0.866025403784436,0.,-0.500000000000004));
#1369=AXIS2_PLACEMENT_3D('',#1366,#1367,#1368);
#1370=PLANE('',#1369);
#1371=ORIENTED_EDGE('',*,*,#613,.T.);
#1372=ORIENTED_EDGE('',*,*,#123,.T.);
#1373=ORIENTED_EDGE('',*,*,#801,.T.);
#1374=DIRECTION('',(0.866025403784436,0.,-0.500000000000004));
#1375=VECTOR('',#1374,1.);
#1376=CARTESIAN_POINT('',(-18.6123113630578,3.3,11.3347202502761));
#1377=LINE('',#1376,#1375);
#1378=EDGE_CURVE('E1136',#612,#791,#1377,.T.);
#1379=ORIENTED_EDGE('',*,*,#1378,.F.);
#1380=EDGE_LOOP('',(#1371,#1372,#1373,#1379));
#1381=FACE_BOUND('',#1380,.T.);
#1382=ADVANCED_FACE('F1026',(#1381),#1370,.F.);
#1383=CARTESIAN_POINT('',(-19.1223113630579,3.3,10.451374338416));
#1384=DIRECTION('',(-0.496519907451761,-0.117779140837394,-0.859997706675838));
#1385=DIRECTION('',(-0.866025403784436,0.,0.500000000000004));
#1386=AXIS2_PLACEMENT_3D('',#1383,#1384,#1385);
#1387=PLANE('',#1386);
#1388=ORIENTED_EDGE('',*,*,#626,.T.);
#1389=DIRECTION('',(0.866025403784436,0.,-0.500000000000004));
#1390=VECTOR('',#1389,1.);
#1391=CARTESIAN_POINT('',(-19.1223113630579,3.3,10.451374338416));
#1392=LINE('',#1391,#1390);
#1393=EDGE_CURVE('E1139',#616,#787,#1392,.T.);
#1394=ORIENTED_EDGE('',*,*,#1393,.T.);
#1395=ORIENTED_EDGE('',*,*,#788,.T.);
#1396=ORIENTED_EDGE('',*,*,#108,.T.);
#1397=EDGE_LOOP('',(#1388,#1394,#1395,#1396));
#1398=FACE_BOUND('',#1397,.T.);
#1399=ADVANCED_FACE('F1021',(#1398),#1387,.F.);
#1400=ORIENTED_EDGE('',*,*,#617,.T.);
#1401=ORIENTED_EDGE('',*,*,#1378,.T.);
#1402=ORIENTED_EDGE('',*,*,#792,.T.);
#1403=ORIENTED_EDGE('',*,*,#1393,.F.);
#1404=EDGE_LOOP('',(#1400,#1401,#1402,#1403));
#1405=FACE_BOUND('',#1404,.T.);
#1406=ADVANCED_FACE('F1024',(#1405),#1112,.F.);
#1407=CARTESIAN_POINT('',(-15.9485281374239,3.3,0.510000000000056));
#1408=DIRECTION('',(0.,-0.117779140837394,0.993039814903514));
#1409=DIRECTION('',(0.,-0.993039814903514,-0.117779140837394));
#1410=AXIS2_PLACEMENT_3D('',#1407,#1408,#1409);
#1411=PLANE('',#1410);
#1412=ORIENTED_EDGE('',*,*,#638,.T.);
#1413=ORIENTED_EDGE('',*,*,#96,.T.);
#1414=ORIENTED_EDGE('',*,*,#776,.T.);
#1415=DIRECTION('',(1.,0.,0.));
#1416=VECTOR('',#1415,1.);
#1417=CARTESIAN_POINT('',(-15.9485281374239,3.3,0.510000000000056));
#1418=LINE('',#1417,#1416);
#1419=EDGE_CURVE('E1087',#637,#766,#1418,.T.);
#1420=ORIENTED_EDGE('',*,*,#1419,.F.);
#1421=EDGE_LOOP('',(#1412,#1413,#1414,#1420));
#1422=FACE_BOUND('',#1421,.T.);
#1423=ADVANCED_FACE('F1057',(#1422),#1411,.F.);
#1424=CARTESIAN_POINT('',(-15.9485281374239,3.3,-0.509999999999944));
#1425=DIRECTION('',(0.,-0.117779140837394,-0.993039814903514));
#1426=DIRECTION('',(0.,0.993039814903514,-0.117779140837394));
#1427=AXIS2_PLACEMENT_3D('',#1424,#1425,#1426);
#1428=PLANE('',#1427);
#1429=ORIENTED_EDGE('',*,*,#651,.T.);
#1430=DIRECTION('',(1.,0.,0.));
#1431=VECTOR('',#1430,1.);
#1432=CARTESIAN_POINT('',(-15.9485281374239,3.3,-0.509999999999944));
#1433=LINE('',#1432,#1431);
#1434=EDGE_CURVE('E1141',#641,#762,#1433,.T.);
#1435=ORIENTED_EDGE('',*,*,#1434,.T.);
#1436=ORIENTED_EDGE('',*,*,#763,.T.);
#1437=ORIENTED_EDGE('',*,*,#81,.T.);
#1438=EDGE_LOOP('',(#1429,#1435,#1436,#1437));
#1439=FACE_BOUND('',#1438,.T.);
#1440=ADVANCED_FACE('F1054',(#1439),#1428,.F.);
#1441=ORIENTED_EDGE('',*,*,#642,.T.);
#1442=ORIENTED_EDGE('',*,*,#1419,.T.);
#1443=ORIENTED_EDGE('',*,*,#767,.T.);
#1444=ORIENTED_EDGE('',*,*,#1434,.F.);
#1445=EDGE_LOOP('',(#1441,#1442,#1443,#1444));
#1446=FACE_BOUND('',#1445,.T.);
#1447=ADVANCED_FACE('F1060',(#1446),#1112,.F.);
#1448=CARTESIAN_POINT('',(-19.1112724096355,3.3,-10.4450009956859));
#1449=DIRECTION('',(-0.496519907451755,-0.117779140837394,0.859997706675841));
#1450=DIRECTION('',(0.86602540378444,0.,0.499999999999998));
#1451=AXIS2_PLACEMENT_3D('',#1448,#1449,#1450);
#1452=PLANE('',#1451);
#1453=ORIENTED_EDGE('',*,*,#663,.T.);
#1454=ORIENTED_EDGE('',*,*,#69,.T.);
#1455=ORIENTED_EDGE('',*,*,#751,.T.);
#1456=DIRECTION('',(0.86602540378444,0.,0.499999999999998));
#1457=VECTOR('',#1456,1.);
#1458=CARTESIAN_POINT('',(-19.1112724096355,3.3,-10.4450009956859));
#1459=LINE('',#1458,#1457);
#1460=EDGE_CURVE('E1142',#662,#741,#1459,.T.);
#1461=ORIENTED_EDGE('',*,*,#1460,.F.);
#1462=EDGE_LOOP('',(#1453,#1454,#1455,#1461));
#1463=FACE_BOUND('',#1462,.T.);
#1464=ADVANCED_FACE('F678',(#1463),#1452,.F.);
#1465=CARTESIAN_POINT('',(-18.6012724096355,3.3,-11.328346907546));
#1466=DIRECTION('',(0.496519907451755,-0.117779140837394,-0.859997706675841));
#1467=DIRECTION('',(-0.86602540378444,0.,-0.499999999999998));
#1468=AXIS2_PLACEMENT_3D('',#1465,#1466,#1467);
#1469=PLANE('',#1468);
#1470=ORIENTED_EDGE('',*,*,#676,.T.);
#1471=DIRECTION('',(0.86602540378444,0.,0.499999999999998));
#1472=VECTOR('',#1471,1.);
#1473=CARTESIAN_POINT('',(-18.6012724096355,3.3,-11.328346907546));
#1474=LINE('',#1473,#1472);
#1475=EDGE_CURVE('E69',#666,#732,#1474,.T.);
#1476=ORIENTED_EDGE('',*,*,#1475,.T.);
#1477=ORIENTED_EDGE('',*,*,#733,.T.);
#1478=ORIENTED_EDGE('',*,*,#49,.T.);
#1479=EDGE_LOOP('',(#1470,#1476,#1477,#1478));
#1480=FACE_BOUND('',#1479,.T.);
#1481=ADVANCED_FACE('F786',(#1480),#1469,.F.);
#1482=ORIENTED_EDGE('',*,*,#667,.T.);
#1483=ORIENTED_EDGE('',*,*,#1460,.T.);
#1484=ORIENTED_EDGE('',*,*,#742,.T.);
#1485=ORIENTED_EDGE('',*,*,#1475,.F.);
#1486=EDGE_LOOP('',(#1482,#1483,#1484,#1485));
#1487=FACE_BOUND('',#1486,.T.);
#1488=ADVANCED_FACE('F699',(#1487),#1112,.F.);
#1489=CARTESIAN_POINT('',(-11.3236812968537,3.3,-18.593191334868));
#1490=DIRECTION('',(-0.859997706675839,-0.117779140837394,0.496519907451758));
#1491=DIRECTION('',(0.500000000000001,0.,0.866025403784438));
#1492=AXIS2_PLACEMENT_3D('',#1489,#1490,#1491);
#1493=PLANE('',#1492);
#1494=ORIENTED_EDGE('',*,*,#373,.T.);
#1495=ORIENTED_EDGE('',*,*,#32,.T.);
#1496=ORIENTED_EDGE('',*,*,#721,.T.);
#1497=DIRECTION('',(0.500000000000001,0.,0.866025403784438));
#1498=VECTOR('',#1497,1.);
#1499=CARTESIAN_POINT('',(-11.3236812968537,3.3,-18.593191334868));
#1500=LINE('',#1499,#1498);
#1501=EDGE_CURVE('E58',#372,#720,#1500,.T.);
#1502=ORIENTED_EDGE('',*,*,#1501,.F.);
#1503=EDGE_LOOP('',(#1494,#1495,#1496,#1502));
#1504=FACE_BOUND('',#1503,.T.);
#1505=ADVANCED_FACE('F677',(#1504),#1493,.F.);
#1506=CARTESIAN_POINT('',(-10.4403353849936,3.3,-19.103191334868));
#1507=DIRECTION('',(0.859997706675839,-0.117779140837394,-0.496519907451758));
#1508=DIRECTION('',(-0.500000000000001,0.,-0.866025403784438));
#1509=AXIS2_PLACEMENT_3D('',#1506,#1507,#1508);
#1510=PLANE('',#1509);
#1511=ORIENTED_EDGE('',*,*,#393,.T.);
#1512=DIRECTION('',(0.500000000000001,0.,0.866025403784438));
#1513=VECTOR('',#1512,1.);
#1514=CARTESIAN_POINT('',(-10.4403353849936,3.3,-19.103191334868));
#1515=LINE('',#1514,#1513);
#1516=EDGE_CURVE('E1147',#381,#1017,#1515,.T.);
#1517=ORIENTED_EDGE('',*,*,#1516,.T.);
#1518=ORIENTED_EDGE('',*,*,#1018,.T.);
#1519=ORIENTED_EDGE('',*,*,#691,.T.);
#1520=EDGE_LOOP('',(#1511,#1517,#1518,#1519));
#1521=FACE_BOUND('',#1520,.T.);
#1522=ADVANCED_FACE('F672',(#1521),#1510,.F.);
#1523=ORIENTED_EDGE('',*,*,#382,.T.);
#1524=ORIENTED_EDGE('',*,*,#1501,.T.);
#1525=ORIENTED_EDGE('',*,*,#1020,.T.);
#1526=ORIENTED_EDGE('',*,*,#1516,.F.);
#1527=EDGE_LOOP('',(#1523,#1524,#1525,#1526));
#1528=FACE_BOUND('',#1527,.T.);
#1529=ADVANCED_FACE('F673',(#1528),#1112,.F.);
#1530=CLOSED_SHELL('',(#60,#87,#114,#141,#168,#195,#222,#249,#276,#303,#330,#358,#684,#706,
#1027,#1044,#1061,#1073,#1090,#1107,#1119,#1136,#1153,#1160,#1177,#1194,#1201,#1218,#1235,#1242,
#1259,#1276,#1283,#1300,#1317,#1324,#1341,#1358,#1365,#1382,#1399,#1406,#1423,#1440,#1447,#1464,
#1481,#1488,#1505,#1522,#1529));
#1531=MANIFOLD_SOLID_BREP('B2',#1530);
#1532=ADVANCED_BREP_SHAPE_REPRESENTATION('',(#18,#1531),#14);
#1533=SHAPE_DEFINITION_REPRESENTATION(#9,#1532);
ENDSEC;
END-ISO-10303-21;
